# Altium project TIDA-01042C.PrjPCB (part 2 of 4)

## Sheet SV601272A-TM4C_Main.SchDoc
size 431 x 279 mm; Date: Not shown in title block; ApprovedBy: Not shown in title block; CheckedBy: Not shown in title block; Author: Not shown in title block; CompanyName: Not shown in title block; Engineer: Not shown in title block; Organization: Not shown in title block; Address1: Not shown in title block; Address2: Not shown in title block; Address3: Not shown in title block; Address4: Not shown in title block; DocumentNumber: 10; Revision: Use project parameter SCH_Rev; SheetNumber: 10; SheetTotal: 11; PageSetup: Record=PageOptions¦CenterHorizontal=True¦CenterVertical=True¦PrintScale=1.00¦XCorrection=1.00¦YCorrection=1.00¦PrintKind=0¦BorderSize=5000000¦LeftOffset=0¦BottomOffset=0¦Orientation=2¦PaperLength=1000¦PaperWidth=1000¦Scale=100¦PaperSource=15¦PrintQuality=600¦MediaType=1¦DitherType=10¦PaperKind=Letter¦PrintScaleMode=1

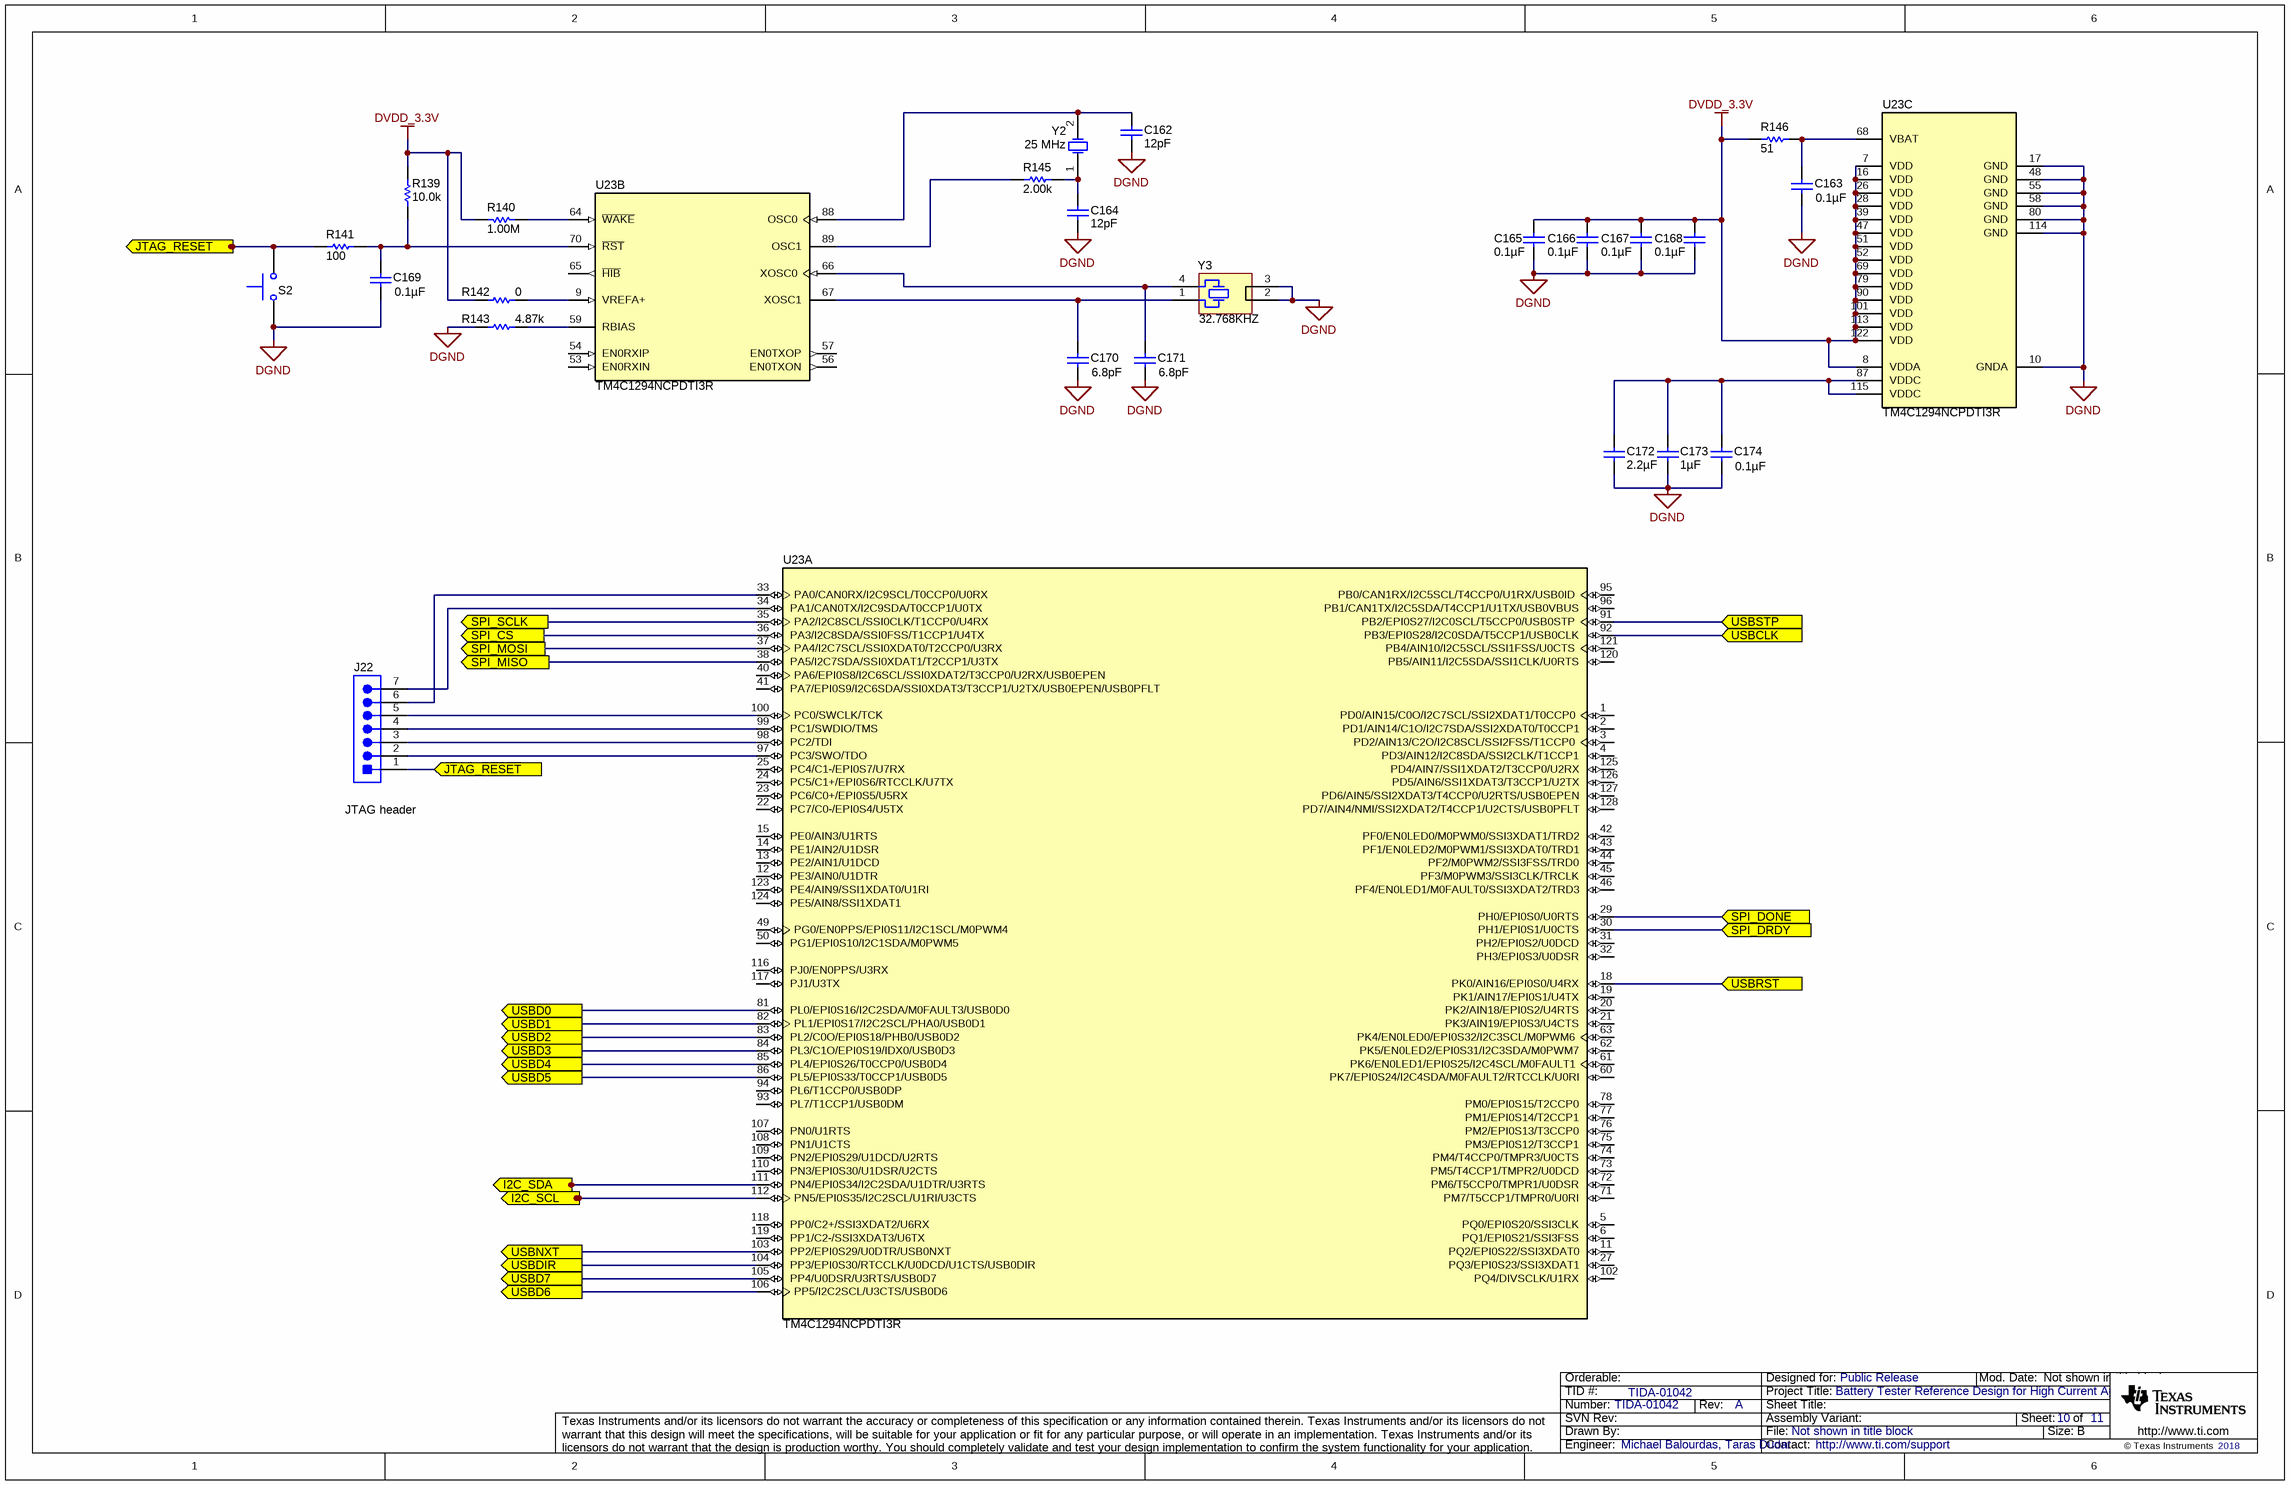
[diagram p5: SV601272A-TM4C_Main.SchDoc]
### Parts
C162  ValueDisplayed: 12pF  [0603]  (hidden comment: C0603C120J5GACTU)
C163  ValueDisplayed: 0.1µF  [0603]  (hidden comment: 06033C104JAT2A)
C164  ValueDisplayed: 12pF  [0603]  (hidden comment: C0603C120J5GACTU)
C165  ValueDisplayed: 0.1µF  [0603]  (hidden comment: 06033C104JAT2A)
C166  ValueDisplayed: 0.1µF  [0603]  (hidden comment: 06033C104JAT2A)
C167  ValueDisplayed: 0.1µF  [0603]  (hidden comment: 06033C104JAT2A)
C168  ValueDisplayed: 0.1µF  [0603]  (hidden comment: 06033C104JAT2A)
C169  ValueDisplayed: 0.1µF  [0603]  (hidden comment: 06033C104JAT2A)
C170  ValueDisplayed: 6.8pF  [0603]  (hidden comment: 06035A6R8CAT2A)
C171  ValueDisplayed: 6.8pF  [0603]  (hidden comment: 06035A6R8CAT2A)
C172  ValueDisplayed: 2.2µF  [0603]  (hidden comment: GRM188R6YA225KA12D)
C173  ValueDisplayed: 1µF  [0603]  (hidden comment: GRM188R71E105KA12D)
C174  ValueDisplayed: 0.1µF  [0603]  (hidden comment: 06033C104JAT2A)
J22  TSW-107-07-G-S  [TSW-107-07-G-S]  (value not drawn)
R139  ValueDisplayed: 10.0k  [0603]  (hidden comment: CRCW060310K0FKEA)
R140  ValueDisplayed: 1.00M  [0603]  (hidden comment: CRCW06031M00FKEA)
R141  ValueDisplayed: 100  [0603]  (hidden comment: CRCW0603100RFKEA)
R142  ValueDisplayed: 0  [0603]  (hidden comment: CRCW06030000Z0EA)
R143  ValueDisplayed: 4.87k  [0603]  (hidden comment: CRCW06034K87FKEA)
R145  ValueDisplayed: 2.00k  [0603]  (hidden comment: CRCW06032K00FKEA)
R146  ValueDisplayed: 51  [0603]  (hidden comment: CRCW060351R0JNEA)
S2  TL1015AF160QG  [SW_TL1015AF160QG]  (value not drawn)
U23  TM4C1294NCPDTI3R  [PDT0128A]  (parts A,B,C of 3)
Y2  Frequency: 25 MHz  [XTAL_ABM3]  (hidden comment: ABM3-25.000MHZ-D2Y-T)
Y3  Frequency: 32.768KHZ  [Seiko_SSP-T]  (hidden comment: SSPT7F-7PF20-R)

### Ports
I2C_SCL, I2C_SDA, JTAG_RESET, SPI_CS, SPI_DONE, SPI_DRDY, SPI_MISO, SPI_MOSI, SPI_SCLK, USBCLK, USBD0, USBD1, USBD2, USBD3, USBD4, USBD5, USBD6, USBD7, USBDIR, USBNXT, USBRST, USBSTP

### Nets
DGND: C162.2 C163.1 C164.2 C165.1 C166.1 C167.1 C168.1 C169.1 C170.1 C171.1 C172.2 C173.2 C174.1 R143.2 S2.1 U23.10(GNDA) U23.17(GND) U23.48(GND) U23.55(GND) U23.58(GND) U23.80(GND) U23.114(GND) Y3.2 Y3.3
DVDD_3.3V: C165.2 C166.2 C167.2 C168.2 R139.2 R140.2 R142.1 R146.1 U23.7(VDD) U23.8(VDDA) U23.16(VDD) U23.26(VDD) U23.28(VDD) U23.39(VDD) U23.47(VDD) U23.51(VDD) U23.52(VDD) U23.69(VDD) U23.79(VDD) U23.90(VDD) U23.101(VDD) U23.113(VDD) U23.122(VDD)
I2C_SCL: U23.112(PN5/EPI0S35/I2C2SCL/U1RI/U3CTS) ; port I2C_SCL
I2C_SDA: U23.111(PN4/EPI0S34/I2C2SDA/U1DTR/U3RTS) ; port I2C_SDA
JTAG_RESET: J22.1 R141.1 S2.2 ; port JTAG_RESET
SPI_CS: U23.36(PA3/I2C8SDA/SSI0FSS/T1CCP1/U4TX) ; port SPI_CS
SPI_DONE: U23.29(PH0/EPI0S0/U0RTS) ; port SPI_DONE
SPI_DRDY: U23.30(PH1/EPI0S1/U0CTS) ; port SPI_DRDY
SPI_MISO: U23.38(PA5/I2C7SDA/SSI0XDAT1/T2CCP1/U3TX) ; port SPI_MISO
SPI_MOSI: U23.37(PA4/I2C7SCL/SSI0XDAT0/T2CCP0/U3RX) ; port SPI_MOSI
SPI_SCLK: U23.35(PA2/I2C8SCL/SSI0CLK/T1CCP0/U4RX) ; port SPI_SCLK
USBCLK: U23.92(PB3/EPI0S28/I2C0SDA/T5CCP1/USB0CLK) ; port USBCLK
USBD0: U23.81(PL0/EPI0S16/I2C2SDA/M0FAULT3/USB0D0) ; port USBD0
USBD1: U23.82(PL1/EPI0S17/I2C2SCL/PHA0/USB0D1) ; port USBD1
USBD2: U23.83(PL2/C0O/EPI0S18/PHB0/USB0D2) ; port USBD2
USBD3: U23.84(PL3/C1O/EPI0S19/IDX0/USB0D3) ; port USBD3
USBD4: U23.85(PL4/EPI0S26/T0CCP0/USB0D4) ; port USBD4
USBD5: U23.86(PL5/EPI0S33/T0CCP1/USB0D5) ; port USBD5
USBD6: U23.106(PP5/I2C2SCL/U3CTS/USB0D6) ; port USBD6
USBD7: U23.105(PP4/U0DSR/U3RTS/USB0D7) ; port USBD7
USBDIR: U23.104(PP3/EPI0S30/RTCCLK/U0DCD/U1CTS/USB0DIR) ; port USBDIR
USBNXT: U23.103(PP2/EPI0S29/U0DTR/USB0NXT) ; port USBNXT
USBRST: U23.18(PK0/AIN16/EPI0S0/U4RX) ; port USBRST
USBSTP: U23.91(PB2/EPI0S27/I2C0SCL/T5CCP0/USB0STP) ; port USBSTP
NetC162_1: C162.1 U23.88(OSC0) Y2.2(OSC2)
NetC163_2: C163.2 R146.2 U23.68(VBAT)
NetC164_1: C164.1 R145.1 Y2.1(OSC1)
NetC169_2: C169.2 R139.1 R141.2 U23.70(~{RST})
NetC170_2: C170.2 U23.67(XOSC1) Y3.1
NetC171_2: C171.2 U23.66(XOSC0) Y3.4
NetC172_1: C172.1 C173.1 C174.2 U23.87(VDDC) U23.115(VDDC)
NetJ22_2: J22.2 U23.97(PC3/SWO/TDO)
NetJ22_3: J22.3 U23.98(PC2/TDI)
NetJ22_4: J22.4 U23.99(PC1/SWDIO/TMS)
NetJ22_5: J22.5 U23.100(PC0/SWCLK/TCK)
NetJ22_6: J22.6 U23.33(PA0/CAN0RX/I2C9SCL/T0CCP0/U0RX)
NetJ22_7: J22.7 U23.34(PA1/CAN0TX/I2C9SDA/T0CCP1/U0TX)
NetR140_1: R140.1 U23.64(~{WAKE})
NetR142_2: R142.2 U23.9(VREFA+)
NetR143_1: R143.1 U23.59(RBIAS)
NetR145_2: R145.2 U23.89(OSC1)

Not connected (* = marked no-connect by the designer): U23 1(PD0/AIN15/C0O/I2C7SCL/SSI2XDAT1/T0CCP0) 2(PD1/AIN14/C1O/I2C7SDA/SSI2XDAT0/T0CCP1) 3(PD2/AIN13/C2O/I2C8SCL/SSI2FSS/T1CCP0) 4(PD3/AIN12/I2C8SDA/SSI2CLK/T1CCP1) 5(PQ0/EPI0S20/SSI3CLK) 6(PQ1/EPI0S21/SSI3FSS) 11(PQ2/EPI0S22/SSI3XDAT0) 12(PE3/AIN0/U1DTR) 13(PE2/AIN1/U1DCD) 14(PE1/AIN2/U1DSR) 15(PE0/AIN3/U1RTS) 19(PK1/AIN17/EPI0S1/U4TX) 20(PK2/AIN18/EPI0S2/U4RTS) 21(PK3/AIN19/EPI0S3/U4CTS) 22(PC7/C0-/EPI0S4/U5TX) 23(PC6/C0+/EPI0S5/U5RX) 24(PC5/C1+/EPI0S6/RTCCLK/U7TX) 25(PC4/C1-/EPI0S7/U7RX) 27(PQ3/EPI0S23/SSI3XDAT1) 31(PH2/EPI0S2/U0DCD) 32(PH3/EPI0S3/U0DSR) 40(PA6/EPI0S8/I2C6SCL/SSI0XDAT2/T3CCP0/U2RX/USB0EPEN) 41(PA7/EPI0S9/I2C6SDA/SSI0XDAT3/T3CCP1/U2TX/USB0EPEN/USB0PFLT) 42(PF0/EN0LED0/M0PWM0/SSI3XDAT1/TRD2) 43(PF1/EN0LED2/M0PWM1/SSI3XDAT0/TRD1) 44(PF2/M0PWM2/SSI3FSS/TRD0) 45(PF3/M0PWM3/SSI3CLK/TRCLK) 46(PF4/EN0LED1/M0FAULT0/SSI3XDAT2/TRD3) 49(PG0/EN0PPS/EPI0S11/I2C1SCL/M0PWM4) 50(PG1/EPI0S10/I2C1SDA/M0PWM5) 53(EN0RXIN) 54(EN0RXIP) 56(EN0TXON) 57(EN0TXOP) 60(PK7/EPI0S24/I2C4SDA/M0FAULT2/RTCCLK/U0RI) 61(PK6/EN0LED1/EPI0S25/I2C4SCL/M0FAULT1) 62(PK5/EN0LED2/EPI0S31/I2C3SDA/M0PWM7) 63(PK4/EN0LED0/EPI0S32/I2C3SCL/M0PWM6) 65(~{HIB}) 71(PM7/T5CCP1/TMPR0/U0RI) 72(PM6/T5CCP0/TMPR1/U0DSR) 73(PM5/T4CCP1/TMPR2/U0DCD) 74(PM4/T4CCP0/TMPR3/U0CTS) 75(PM3/EPI0S12/T3CCP1) 76(PM2/EPI0S13/T3CCP0) 77(PM1/EPI0S14/T2CCP1) 78(PM0/EPI0S15/T2CCP0) 93(PL7/T1CCP1/USB0DM) 94(PL6/T1CCP0/USB0DP) 95(PB0/CAN1RX/I2C5SCL/T4CCP0/U1RX/USB0ID) 96(PB1/CAN1TX/I2C5SDA/T4CCP1/U1TX/USB0VBUS) 102(PQ4/DIVSCLK/U1RX) 107(PN0/U1RTS) 108(PN1/U1CTS) 109(PN2/EPI0S29/U1DCD/U2RTS) 110(PN3/EPI0S30/U1DSR/U2CTS) 116(PJ0/EN0PPS/U3RX) 117(PJ1/U3TX) 118(PP0/C2+/SSI3XDAT2/U6RX) 119(PP1/C2-/SSI3XDAT3/U6TX) 120(PB5/AIN11/I2C5SDA/SSI1CLK/U0RTS) 121(PB4/AIN10/I2C5SCL/SSI1FSS/U0CTS) 123(PE4/AIN9/SSI1XDAT0/U1RI) 124(PE5/AIN8/SSI1XDAT1) 125(PD4/AIN7/SSI1XDAT2/T3CCP0/U2RX) 126(PD5/AIN6/SSI1XDAT3/T3CCP1/U2TX) 127(PD6/AIN5/SSI2XDAT3/T4CCP0/U2RTS/USB0EPEN) 128(PD7/AIN4/NMI/SSI2XDAT2/T4CCP1/U2CTS/USB0PFLT)

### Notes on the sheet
- (near J22) JTAG header

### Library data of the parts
C162 C164 = C0603C120J5GACTU: CAP, CERM, 12 pF, 50 V, +/- 5%, C0G/NP0, 0603; Manufacturer: Kemet; Polarized: N; CompType: Capacitor; Value: 12pF; U/M: EA; Cap_F: 0.000000000012; Tolerance_%: 5; Value1: Unknown; VDC_V: 50; Value2: 50V; TaMin_C: -55; TaMax_C: 125; AEC Category: Q200
C163 C165-C169 C174 = 06033C104JAT2A: CAP, CERM, 0.1 µF, 25 V, +/- 5%, X7R, 0603; Manufacturer: AVX; Polarized: N; CompType: Capacitor; Value: 0.1uF; U/M: EA; Cap_F: 0.0000001; Tolerance_%: 5; ESR_ohm: 0.05; Value1: 0.05 ohm; VDC_V: 25; Value2: 25V; TaMin_C: -55; TaMax_C: 125; AEC Category: Q200
C170 C171 = 06035A6R8CAT2A: CAP, CERM, 6.8 pF, 50 V, +/- 4%, C0G/NP0, 0603; Manufacturer: AVX; Polarized: N; CompType: Capacitor; Value: 6.8pF; U/M: EA; Cap_F: 0.0000000000068; Tolerance_%: 4; ESR_ohm: 0.505; Value1: 0.505 ohm; VDC_V: 50; Value2: 50V; TaMin_C: -55; TaMax_C: 125; AEC Category: Q200
C172 = GRM188R6YA225KA12D: CAP, CERM, 2.2 µF, 35 V, +/- 10%, X5R, 0603; Manufacturer: MuRata; Polarized: N; CompType: Capacitor; Value: 2.2uF; U/M: EA; Cap_F: 0.0000022; Tolerance_%: 10; Value1: Unknown; VDC_V: 35; Value2: 35V; TaMin_C: -55; TaMax_C: 85; AEC Category: Q200
C173 = GRM188R71E105KA12D: CAP, CERM, 1 µF, 25 V, +/- 10%, X7R, 0603; Manufacturer: MuRata; Polarized: N; CompType: Capacitor; Value: 1uF; U/M: EA; Cap_F: 0.000001; Tolerance_%: 10; Value1: Unknown; VDC_V: 25; Value2: 25V; TaMin_C: -55; TaMax_C: 125; AEC Category: Q200
J22 = TSW-107-07-G-S: Header, 100mil, 7x1, Gold, TH; Manufacturer: Samtec; SymbolCreator: a0411947; U/M: EA
R139 = CRCW060310K0FKEA: RES, 10.0 k, 1%, 0.1 W, 0603; Manufacturer: Vishay-Dale; CompType: Resistor; Value: 10.0k; Res_ohm: 10000; Value_Code: 10k0; Tolerance_%: 1; Power_W: 0.1; Value2: 0.1W; VDC_V: 75; TempCo: 100 ppm/C; EIA_Code: E96; U/M: EA; AEC Category: Q200
R140 = CRCW06031M00FKEA: RES, 1.00 M, 1%, 0.1 W, 0603; Manufacturer: Vishay-Dale; CompType: Resistor; Value: 1.00Meg; Res_ohm: 1000000; Value_Code: 1M00; Tolerance_%: 1; Power_W: 0.1; Value2: 0.1W; VDC_V: 75; TempCo: 100 ppm/C; EIA_Code: E96; U/M: EA; AEC Category: Q200
R141 = CRCW0603100RFKEA: RES, 100, 1%, 0.1 W, 0603; Manufacturer: Vishay-Dale; CompType: Resistor; Value: 100; Value_Code: 100R; Tolerance_%: 1; Power_W: 0.1; Value2: 0.1W; VDC_V: 75; TempCo: 100 ppm/C; EIA_Code: E96; U/M: EA; AEC Category: Q200
R142 = CRCW06030000Z0EA: RES, 0, 5%, 0.1 W, 0603; Manufacturer: Vishay-Dale; CompType: Resistor; Value: 0; Value_Code: 0000; Tolerance_%: 5; Power_W: 0.1; Value2: 0.1W; VDC_V: 75; TempCo: 200 ppm/C; EIA_Code: E24; U/M: EA; AEC Category: Q200
R143 = CRCW06034K87FKEA: RES, 4.87 k, 1%, 0.1 W, 0603; Manufacturer: Vishay-Dale; CompType: Resistor; Value: 4.87k; Res_ohm: 4870; Value_Code: 4k87; Tolerance_%: 1; Power_W: 0.1; Value2: 0.1W; VDC_V: 75; TempCo: 100 ppm/C; EIA_Code: E96; U/M: EA; AEC Category: Q200
R145 = CRCW06032K00FKEA: RES, 2.00 k, 1%, 0.1 W, 0603; Manufacturer: Vishay-Dale; CompType: Resistor; Value: 2.00k; Res_ohm: 2000; Value_Code: 2k00; Tolerance_%: 1; Power_W: 0.1; Value2: 0.1W; VDC_V: 75; TempCo: 100 ppm/C; EIA_Code: E96; U/M: EA; AEC Category: Q200
R146 = CRCW060351R0JNEA: RES, 51, 5%, 0.1 W, 0603; Manufacturer: Vishay-Dale; CompType: Resistor; Value: 51; Value_Code: 51R0; Tolerance_%: 5; Power_W: 0.1; Value2: 0.1W; VDC_V: 75; TempCo: 200 ppm/C; EIA_Code: E24; U/M: EA; AEC Category: Q200
S2 = TL1015AF160QG: Switch, Tactile, SPST-NO, 0.05A, 12V, SMT; Manufacturer: E-Switch; SymbolCreator: a0412235; VDC_V: 12; SwitchFunction: Off-Mom; PositionCount: 1; CurrentRating_mA: 50
U23 = CMP-0029864-2: Tiva C Series Microcontroller, 1024 KB Flash, 256 KB SRAM, 12 Bit, 20 Channels, -40 to 85 degC, 128-Pin TQFP (PDT), Green (RoHS & no Sb/Br), Tape and Reel; Manufacturer: Texas Instruments; ADC Channels: 20; CPU: ARM Cortex-M4; Flash: 1024 KB; ADC Resolution: 12 Bits; Max Speed: 120 MHz; SRAM: 256 KB; SizeAreaWB_mm2: 324.0; SizeArea_mm2: 256.0; SizeX_mm: 16.0; SizeZ_mm: 1.2; CompType: IC
Y2 = ABM3-25.000MHZ-D2Y-T: Crystal, 25 MHz, 18 pF, SMD; Manufacturer: Abracon Corportation; SymbolCreator: a0412235; U/M: EA; TaMin_C: -40; TaMax_C: 85; Frequency Stability: ±30ppm
Y3 = SSPT7F-7PF20-R: CRYSTAL, 32.768KHZ, 7PF, SMD; Manufacturer: Seiko Instruments; SymbolCreator: x0208325; U/M: EA; TaMin_C: -40; TaMax_C: 85; Frequency Stability: ±20ppm

## Sheet SV601272A-TM4C_Power.SchDoc
size 431 x 279 mm; Date: Not shown in title block; ApprovedBy: Not shown in title block; CheckedBy: Not shown in title block; Author: Not shown in title block; CompanyName: Not shown in title block; Engineer: Not shown in title block; Organization: Not shown in title block; Address1: Not shown in title block; Address2: Not shown in title block; Address3: Not shown in title block; Address4: Not shown in title block; DocumentNumber: 11; Revision: Use project parameter SCH_Rev; SheetNumber: 11; SheetTotal: 11; PageSetup: Record=PageOptions¦CenterHorizontal=True¦CenterVertical=True¦PrintScale=1.00¦XCorrection=1.00¦YCorrection=1.00¦PrintKind=0¦BorderSize=5000000¦LeftOffset=0¦BottomOffset=0¦Orientation=2¦PaperLength=1000¦PaperWidth=1000¦Scale=100¦PaperSource=15¦PrintQuality=600¦MediaType=1¦DitherType=10¦PaperKind=Letter¦PrintScaleMode=1

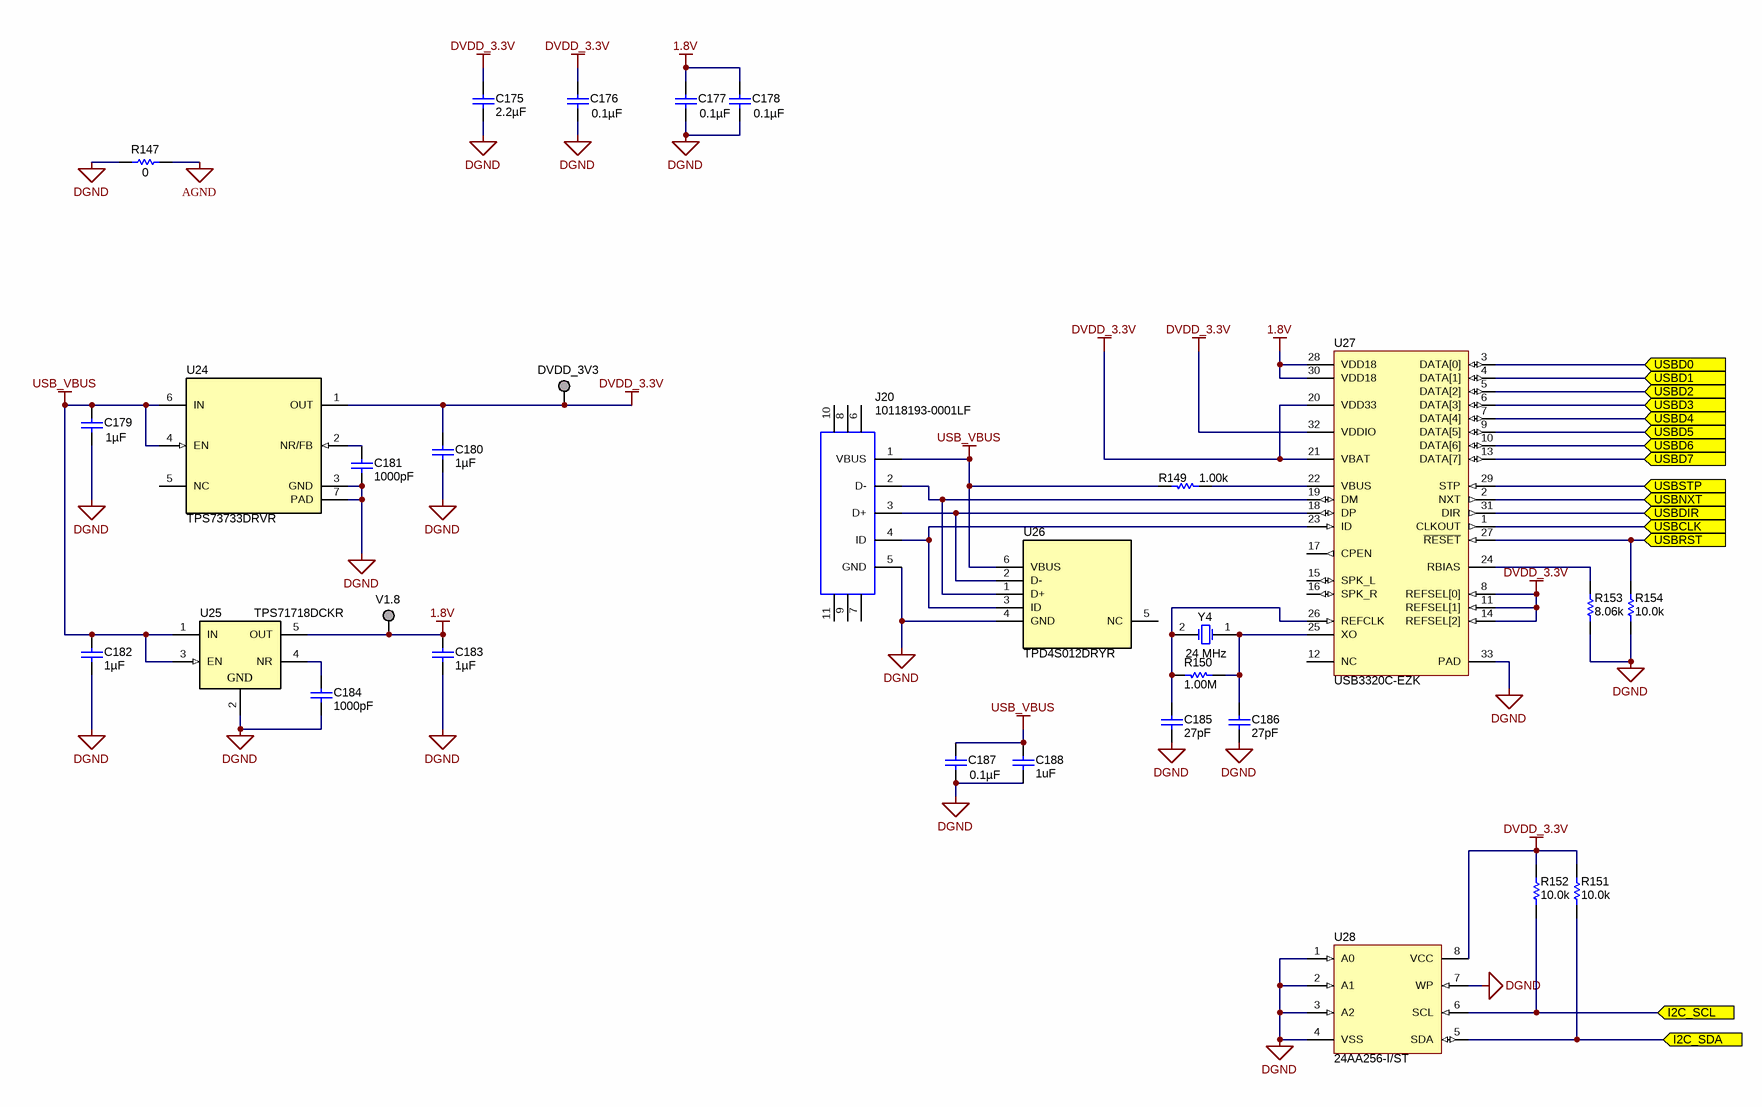
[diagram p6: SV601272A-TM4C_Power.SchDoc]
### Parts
C175  ValueDisplayed: 2.2µF  [0603]  (hidden comment: GRM188R6YA225KA12D)
C176  ValueDisplayed: 0.1µF  [0603]  (hidden comment: 06033C104JAT2A)
C177  ValueDisplayed: 0.1µF  [0603]  (hidden comment: 06033C104JAT2A)
C178  ValueDisplayed: 0.1µF  [0603]  (hidden comment: 06033C104JAT2A)
C179  ValueDisplayed: 1µF  [0603]  (hidden comment: GRM188R71E105KA12D)
C180  ValueDisplayed: 1µF  [0603]  (hidden comment: GRM188R71E105KA12D)
C181  ValueDisplayed: 1000pF  [0603]  (hidden comment: 06031C102JAT2A)
C182  ValueDisplayed: 1µF  [0603]  (hidden comment: GRM188R71E105KA12D)
C183  ValueDisplayed: 1µF  [0603]  (hidden comment: GRM188R71E105KA12D)
C184  ValueDisplayed: 1000pF  [0603]  (hidden comment: 06031C102JAT2A)
C185  ValueDisplayed: 27pF  [0603]  (hidden comment: 06035A270JAT2A)
C186  ValueDisplayed: 27pF  [0603]  (hidden comment: 06035A270JAT2A)
C187  ValueDisplayed: 0.1µF  [0603]  (hidden comment: 06033C104JAT2A)
C188  ValueDisplayed: 1uF  [0603]  (hidden comment: Capacitor)
DVDD_3V3  Pogo Pad  [PogoPad]  (value not drawn)  (no BOM)
J20  10118193-0001LF  [FCI_10118193-0001LF]
R147  ValueDisplayed: 0  [0603]  (hidden comment: Resistor)
R149  ValueDisplayed: 1.00k  [0603]  (hidden comment: CRCW06031K00FKEA)
R150  ValueDisplayed: 1.00M  [0603]  (hidden comment: CRCW06031M00FKEA)
R151  ValueDisplayed: 10.0k  [0603]  (hidden comment: CRCW060310K0FKEA)
R152  ValueDisplayed: 10.0k  [0603]  (hidden comment: CRCW060310K0FKEA)
R153  ValueDisplayed: 8.06k  [0603]  (hidden comment: CRCW06038K06FKEA)
R154  ValueDisplayed: 10.0k  [0603]  (hidden comment: CRCW060310K0FKEA)
U24  TPS73733DRVR  [DRV0006A]
U25  TPS71718DCKR  [DCK0005A_N]
U26  TPD4S012DRYR  [DRY0006A]
U27  USB3320C-EZK  [Microchip_32QFN-3304-5x5B]
U28  24AA256-I/ST  [TSSOP-8]
V1.8  Pogo Pad  [PogoPad]  (value not drawn)  (no BOM)
Y4  Frequency: 24 MHz  [XTAL_ABM3]  (hidden comment: ABM3-24.000MHZ-D2Y-T)

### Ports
I2C_SCL, I2C_SDA, USBCLK, USBD0, USBD1, USBD2, USBD3, USBD4, USBD5, USBD6, USBD7, USBDIR, USBNXT, USBRST, USBSTP

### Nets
1.8V: C177.2 C178.2 C183.1 U25.5(OUT) U27.28(VDD18) U27.30(VDD18) V1.8.1
AGND: R147.2
DGND: C175.2 C176.1 C177.1 C178.1 C179.2 C180.2 C181.2 C182.2 C183.2 C184.2 C185.1 C186.1 C187.1 C188.2 J20.5(GND) R147.1 R153.1 R154.1 U24.3(GND) U24.7(PAD) U25.2(GND) U26.4(GND) U27.33(PAD) U28.1(A0) U28.2(A1) U28.3(A2) U28.4(VSS) U28.7(WP)
DVDD_3.3V: C175.1 C176.2 C180.1 DVDD_3V3.1 R151.2 R152.2 U24.1(OUT) U27.8(REFSEL[0]) U27.11(REFSEL[1]) U27.14(REFSEL[2]) U27.20(VDD33) U27.21(VBAT) U27.32(VDDIO) U28.8(VCC)
USB_VBUS: C179.1 C182.1 C187.2 C188.1 J20.1(VBUS) R149.2 U24.4(EN) U24.6(IN) U25.1(IN) U25.3(EN) U26.6(VBUS)
I2C_SCL: R152.1 U28.6(SCL) ; port I2C_SCL
I2C_SDA: R151.1 U28.5(SDA) ; port I2C_SDA
USBCLK: U27.1(CLKOUT) ; port USBCLK
USBD0: U27.3(DATA[0]) ; port USBD0
USBD1: U27.4(DATA[1]) ; port USBD1
USBD2: U27.5(DATA[2]) ; port USBD2
USBD3: U27.6(DATA[3]) ; port USBD3
USBD4: U27.7(DATA[4]) ; port USBD4
USBD5: U27.9(DATA[5]) ; port USBD5
USBD6: U27.10(DATA[6]) ; port USBD6
USBD7: U27.13(DATA[7]) ; port USBD7
USBDIR: U27.31(DIR) ; port USBDIR
USBNXT: U27.2(NXT) ; port USBNXT
USBRST: R154.2 U27.27(~{RESET}) ; port USBRST
USBSTP: U27.29(STP) ; port USBSTP
NetC181_1: C181.1 U24.2(NR/FB)
NetC184_1: C184.1 U25.4(NR)
NetC185_2: C185.2 R150.2 U27.26(REFCLK) Y4.2(OSC2)
NetC186_2: C186.2 R150.1 U27.25(XO) Y4.1(OSC1)
NetJ20_2: J20.2(D-) U26.1(D+) U27.19(DM)
NetJ20_3: J20.3(D+) U26.2(D-) U27.18(DP)
NetJ20_4: J20.4(ID) U26.3(ID) U27.23(ID)
NetR149_1: R149.1 U27.22(VBUS)
NetR153_2: R153.2 U27.24(RBIAS)

Not connected (* = marked no-connect by the designer): J20 6 7 8 9 10 11; U24 5(NC); U26 5(NC); U27 12(NC) 15(SPK_L) 16(SPK_R) 17(CPEN)

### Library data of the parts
C175 = GRM188R6YA225KA12D: as C172 on sheet SV601272A-TM4C_Main
C176-C178 C187 = 06033C104JAT2A: as C163 on sheet SV601272A-TM4C_Main
C179 C180 C182 C183 = GRM188R71E105KA12D: as C173 on sheet SV601272A-TM4C_Main
C181 C184 = 06031C102JAT2A: CAP, CERM, 1000 pF, 100 V, +/- 5%, X7R, 0603; Manufacturer: AVX; Polarized: N; CompType: Capacitor; Value: 1000pF; U/M: EA; Cap_F: 0.000000001; Tolerance_%: 5; ESR_ohm: 0.276; Value1: 0.276 ohm; VDC_V: 100; Value2: 100V; TaMin_C: -55; TaMax_C: 125; AEC Category: Q200
C185 C186 = 06035A270JAT2A: CAP, CERM, 27 pF, 50 V, +/- 5%, C0G/NP0, 0603; Manufacturer: AVX; Polarized: N; CompType: Capacitor; Value: 27pF; U/M: EA; Cap_F: 0.000000000027; Tolerance_%: 5; ESR_ohm: 0.232; Value1: 0.232 ohm; VDC_V: 50; Value2: 50V; TaMin_C: -55; TaMax_C: 125; AEC Category: Q200
C188 = CMP-0007405-4: CAP, CERM, 1 uF, 25 V, +/- 10%, X7R, 0603; PartNumber: GRM188R71E105KA12D; Manufacturer: MuRata; Polarized: N; Value: 1uF; U/M: EA; Cap_F: 1µF; Value1: Unknown; VDC_V: 25V; TaMin_C: -55°C; TaMax_C: 125°C; AEC Category: Q200; SizeArea_mm2: 1.28; SizeAreaWB_mm2: 4.68; SizeX_mm: 1.6; SizeY_mm: 0.8; SizeZ_mm: 1
DVDD_3V3 V1.8 = PogoPad: Pad for Pogo Pin Connector; SymbolCreator: codlsc
J20 = CMP-0065029-1: Connector, Receptacle, USB Micro B, R/A, SMT; Manufacturer: FCI; CNHeader: False; Gender: Female; Row_Count: 1; Pitch_mm: 0.65; ContactFinish: Gold; CT: True
R147 = CMP-0025874-3: RES, 0, 5%, 0.1 W, 0603; PartNumber: ERJ-3GEY0R00V; Manufacturer: Panasonic; Value: 0; Value_Code: 0000; Power_W: 100mW; Value2: 0.1W; VDC_V: 50V; TempCo: 600 ppm/C; EIA_Code: E24; U/M: EA; AEC Category: Q200; SizeArea_mm2: 1.28; SizeX_mm: 1.6; SizeY_mm: 0.8; SizeZ_mm: 1
R149 = CRCW06031K00FKEA: RES, 1.00 k, 1%, 0.1 W, 0603; Manufacturer: Vishay-Dale; CompType: Resistor; Value: 1.00k; Res_ohm: 1000; Value_Code: 1k00; Tolerance_%: 1; Power_W: 0.1; Value2: 0.1W; VDC_V: 75; TempCo: 100 ppm/C; EIA_Code: E96; U/M: EA; AEC Category: Q200
R150 = CRCW06031M00FKEA: as R140 on sheet SV601272A-TM4C_Main
R151 R152 R154 = CRCW060310K0FKEA: as R139 on sheet SV601272A-TM4C_Main
R153 = CRCW06038K06FKEA: RES, 8.06 k, 1%, 0.1 W, 0603; Manufacturer: Vishay-Dale; CompType: Resistor; Value: 8.06k; Res_ohm: 8060; Value_Code: 8k06; Tolerance_%: 1; Power_W: 0.1; Value2: 0.1W; VDC_V: 75; TempCo: 100 ppm/C; EIA_Code: E96; U/M: EA; AEC Category: Q200
U24 = TPS73733DRVR: 1-A Low-Dropout Regulator With Reverse Current Protection, DRV0006A; Manufacturer: Texas Instruments; Alternate PartNumber: TPS73733DRVT; SymbolCreator: a0411947; CompType: IC; U/M: EA
U25 = TPS71718DCKR: Single Output High PSRR LDO, 150 mA, Fixed 1.8 V Output, 2.5 to 6.5 V Input, with Low IQ, 5-pin SC70 (DCK), -40 to 85 degC, Green (RoHS & no Sb/Br); Manufacturer: Texas Instruments; Alternate PartNumber: Equivalent; Accuracy(%): 3; Fixed Output Options(V): 1.8; Iout(Max)(A): 0.15; Iq(Typ)(mA): 0.05; SubFamily: Single Channel LDO; Vdo(Typ)(mV): 170; Vin(Max)(V): 6.5; Vin(Min)(V): 2.5
U26 = CMP-0043122-2: USB ESD Solution with Power Clamp, 4 Channels, -40 to +85 degC, 6-pin SON (DRY), Green (RoHS & no Sb/Br); Manufacturer: Texas Instruments; IO Leakage Current(nA): 10; USB High Speed: TRUE; Breakdown Voltage(Min)(V): 6; IO Capacitance(Typ)(pF): 0.8; AEC Category: Q200; AEC Qualified: N; CompType: IC; SizeAreaWB_mm2: 4.9; SizeArea_mm2: 1.45; SizeX_mm: 1.0; SizeZ_mm: 0.6
U27 = USB3320C-EZK: Highly Integrated Full Featured Hi-Speed USB 2.0 ULPI Transceiver, QFN-32; Manufacturer: Microchip; SymbolCreator: Altium
U28 = 24AA256-I/ST: 256K I2C™ CMOS Serial EEPROM, TSSOP-8; Manufacturer: Microchip; SymbolCreator: a0411947
Y4 = ABM3-24.000MHZ-D2Y-T: Crystal, 24 MHz, 18 pF, SMD; Manufacturer: Abracon Corportation; SymbolCreator: a0412235; U/M: EA; TaMin_C: -40; TaMax_C: 85; Frequency Stability: ±30ppm

## Sheet SV601272A-Controller2.SchDoc: Controller
size 431 x 279 mm; Date: Not shown in title block; ApprovedBy: Not shown in title block; CheckedBy: Not shown in title block; Author: Not shown in title block; CompanyName: Not shown in title block; Engineer: Not shown in title block; Organization: Not shown in title block; Address1: Not shown in title block; Address2: Not shown in title block; Address3: Not shown in title block; Address4: Not shown in title block; DocumentNumber: 4; Revision: Use project parameter SCH_Rev; SheetNumber: 4; SheetTotal: 11; PageSetup: Record=PageOptions¦CenterHorizontal=True¦CenterVertical=True¦PrintScale=1.00¦XCorrection=1.00¦YCorrection=1.00¦PrintKind=0¦BorderSize=5000000¦LeftOffset=0¦BottomOffset=0¦Orientation=2¦PaperLength=1000¦PaperWidth=1000¦Scale=100¦PaperSource=15¦PrintQuality=600¦MediaType=1¦DitherType=10¦PaperKind=Letter¦PrintScaleMode=1

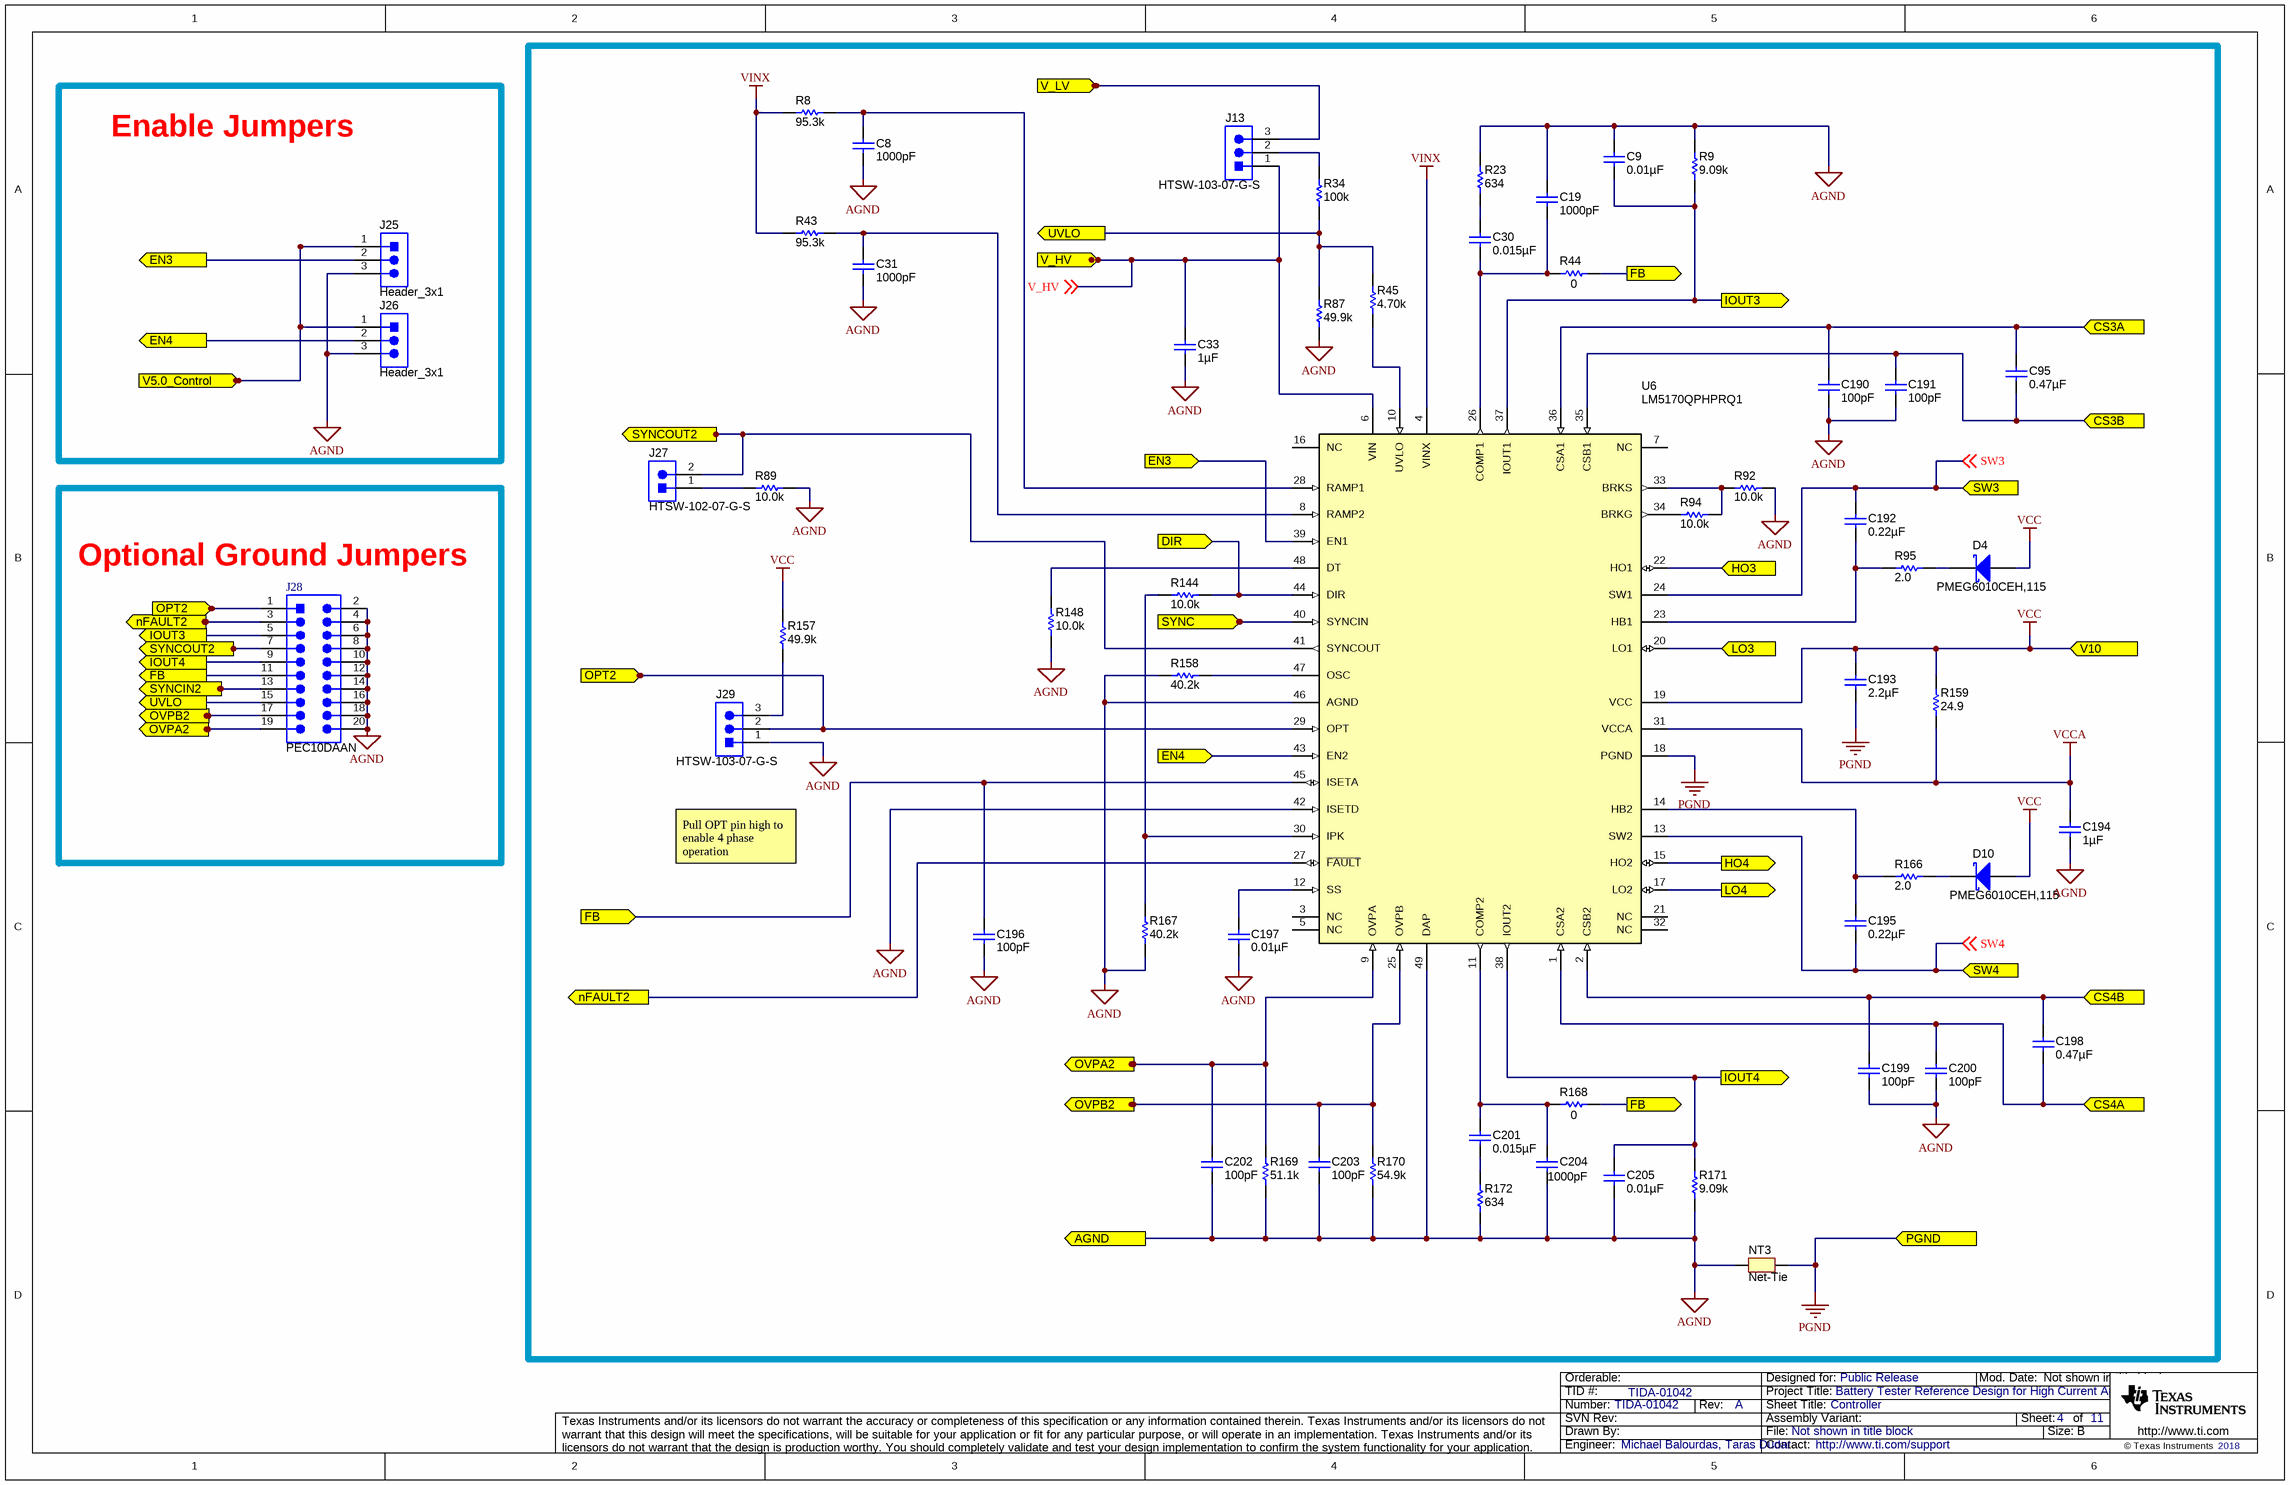
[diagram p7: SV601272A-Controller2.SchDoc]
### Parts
C8  ValueDisplayed: 1000pF  [0603L]  (hidden comment: C1608C0G2A102J080AA)
C9  ValueDisplayed: 0.01µF  [0603L]  (hidden comment: 06031C103KAT2A)
C19  ValueDisplayed: 1000pF  [0603L]  (hidden comment: C1608C0G2A102J080AA)
C30  ValueDisplayed: 0.015µF  [0603L]  (hidden comment: GRM188R71E153KA01D)
C31  ValueDisplayed: 1000pF  [0603L]  (hidden comment: C1608C0G2A102J080AA)
C33  ValueDisplayed: 1µF  [0805_HV]  (hidden comment: C2012X7S2A105K125AB)
C95  ValueDisplayed: 0.47µF  [0603L]  (hidden comment: GRM188R71C474KA88D)
C190  ValueDisplayed: 100pF  [0603L]  (hidden comment: C0603C101J5GACTU)
C191  ValueDisplayed: 100pF  [0603L]  (hidden comment: C0603C101J5GACTU)
C192  ValueDisplayed: 0.22µF  [0603L]  (hidden comment: C1608X7R1H224K080AB)
C193  ValueDisplayed: 2.2µF  [0805_HV]  (hidden comment: C2012X7R1C225K125AB)
C194  ValueDisplayed: 1µF  [0603L]  (hidden comment: GRM188R71E105KA12D)
C195  ValueDisplayed: 0.22µF  [0603L]  (hidden comment: C1608X7R1H224K080AB)
C196  ValueDisplayed: 100pF  [0603L]  (hidden comment: C0603C101J5GACTU)
C197  ValueDisplayed: 0.01µF  [0603L]  (hidden comment: 06031C103KAT2A)
C198  ValueDisplayed: 0.47µF  [0603L]  (hidden comment: GRM188R71C474KA88D)
C199  ValueDisplayed: 100pF  [0603L]  (hidden comment: C0603C101J5GACTU)
C200  ValueDisplayed: 100pF  [0603L]  (hidden comment: C0603C101J5GACTU)
C201  ValueDisplayed: 0.015µF  [0603L]  (hidden comment: GRM188R71E153KA01D)
C202  ValueDisplayed: 100pF  [0603L]  (hidden comment: C0603C101J5GACTU)
C203  ValueDisplayed: 100pF  [0603L]  (hidden comment: C0603C101J5GACTU)
C204  ValueDisplayed: 1000pF  [0603L]  (hidden comment: C1608C0G2A102J080AA)
C205  ValueDisplayed: 0.01µF  [0603L]  (hidden comment: 06031C103KAT2A)
D4  PMEG6010CEH,115  [SOD-123F]
D10  PMEG6010CEH,115  [SOD-123F]
J13  HTSW-103-07-G-S  [Samtec_HTSW-103-07-G-S]
J25  Header_3x1  [Samtec_HTSW-103-07-G-S]
J26  Header_3x1  [Samtec_HTSW-103-07-G-S]
J27  HTSW-102-07-G-S  [Samtec_HTSW-102-07-G-S]
J28  PEC10DAAN  [SULLINS_PEC10DAAN]
J29  HTSW-103-07-G-S  [Samtec_HTSW-103-07-G-S]
NT3  Net-Tie  [Net-Tie_10mil]  (net tie, no BOM)
R8  ValueDisplayed: 95.3k  [0603L]  (hidden comment: CRCW060395K3FKEA)
R9  ValueDisplayed: 9.09k  [0603L]  (hidden comment: CRCW06039K09FKEA)
R23  ValueDisplayed: 634  [0603L]  (hidden comment: CRCW0603634RFKEA)
R34  ValueDisplayed: 100k  [0603]  (hidden comment: CRCW0603100KFKEA)
R43  ValueDisplayed: 95.3k  [0603L]  (hidden comment: CRCW060395K3FKEA)
R44  ValueDisplayed: 0  [0603]  (hidden comment: Resistor)
R45  ValueDisplayed: 4.70k  [0603]  (hidden comment: RC0603FR-074K7L)
R87  ValueDisplayed: 49.9k  [0603]  (hidden comment: ERJ-3EKF4992V)
R89  ValueDisplayed: 10.0k  [0603L]  (hidden comment: CRCW060310K0FKEA)
R92  ValueDisplayed: 10.0k  [0603]  (hidden comment: ERJ-3EKF1002V)
R94  ValueDisplayed: 10.0k  [0603]  (hidden comment: ERJ-3EKF1002V)
R95  ValueDisplayed: 2.0  [0805_HV]  (hidden comment: CRCW08052R00JNEA)
R144  ValueDisplayed: 10.0k  [0603L]  (hidden comment: CRCW060310K0FKEA)
R148  ValueDisplayed: 10.0k  [0603L]  (hidden comment: CRCW060310K0FKEA)
R157  ValueDisplayed: 49.9k  [0603L]  (hidden comment: CRCW060349K9FKEA)
R158  ValueDisplayed: 40.2k  [0603L]  (hidden comment: CRCW060340K2FKEA)
R159  ValueDisplayed: 24.9  [0805L]  (hidden comment: CRCW080524R9FKEA)
R166  ValueDisplayed: 2.0  [0805_HV]  (hidden comment: CRCW08052R00JNEA)
R167  ValueDisplayed: 40.2k  [0603]  (hidden comment: ERJ-3EKF4022V)
R168  ValueDisplayed: 0  [0603]  (hidden comment: Resistor)
R169  ValueDisplayed: 51.1k  [0603L]  (hidden comment: CRCW060351K1FKEA)
R170  ValueDisplayed: 54.9k  [0603L]  (hidden comment: CRCW060354K9FKEA)
R171  ValueDisplayed: 9.09k  [0603L]  (hidden comment: CRCW06039K09FKEA)
R172  ValueDisplayed: 634  [0603L]  (hidden comment: CRCW0603634RFKEA)
U6  LM5170QPHPRQ1  [PHP0048D_L]

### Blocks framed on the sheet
Enable Jumpers: J25 J26
Optional Ground Jumpers: J28

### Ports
AGND, CS3A, CS3B, CS4A, CS4B, DIR, EN3, EN4, FB, HO3, HO4, IOUT3, IOUT4, LO3, LO4, nFAULT2, OPT2, OVPA2, OVPB2, PGND, SW3, SW4, SYNC, SYNCIN2, SYNCOUT2, UVLO, V5.0_Control, V10, V_HV, V_LV

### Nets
AGND: C8.2 C9.1 C19.1 C31.2 C33.2 C190.2 C191.2 C194.2 C196.2 C197.2 C199.2 C200.2 C202.2 C203.2 C204.2 C205.2 J25.3 J26.3 J28.2 J28.4 J28.6 J28.8 J28.10 J28.12 J28.14 J28.16 J28.18 J28.20 J29.1 NT3.1 R9.2 R23.2 R87.1 R89.2 R92.1 R148.1 R158.1 R167.1 R169.1 R170.1 R171.1 R172.1 U6.42(ISETD) U6.46(AGND) U6.49(DAP) ; port AGND
PGND: C193.2 NT3.2 U6.18(PGND) ; port PGND
V_HV: C33.1 J13.1 U6.6(VIN) ; off-sheet V_HV, port V_HV
V_LV: J13.3 ; port V_LV
VCC: C193.1 D4.2(A) D10.2(A) R157.2 R159.2 U6.19(VCC) ; port V10
VCCA: C194.1 R159.1 U6.31(VCCA)
VINX: R8.1 R43.1 U6.4(VINX)
CS3A: C95.1 C190.1 U6.36(CSA1) ; port CS3A
CS3B: C95.2 C191.1 U6.35(CSB1) ; port CS3B
CS4A: C198.2 C200.1 U6.1(CSA2) ; port CS4A
CS4B: C198.1 C199.1 U6.2(CSB2) ; port CS4B
DIR: R144.2 U6.44(DIR) ; port DIR
EN3: J25.2 U6.39(EN1) ; port EN3
EN4: J26.2 U6.43(EN2) ; port EN4
FB: C196.1 J28.11 R44.2 R168.2 U6.45(ISETA) ; port FB
HO3: U6.22(HO1) ; port HO3
HO4: U6.15(HO2) ; port HO4
IOUT3: C9.2 J28.5 R9.1 U6.37(IOUT1) ; port IOUT3
IOUT4: C205.1 J28.9 R171.2 U6.38(IOUT2) ; port IOUT4
LO3: U6.20(LO1) ; port LO3
LO4: U6.17(LO2) ; port LO4
nFAULT2: J28.3 U6.27(~{FAULT}) ; port nFAULT2
OPT2: J28.1 J29.2 U6.29(OPT) ; port OPT2
OVPA2: C202.1 J28.19 R169.2 U6.9(OVPA) ; port OVPA2
OVPB2: C203.1 J28.17 R170.2 U6.25(OVPB) ; port OVPB2
SW3: C192.1 U6.24(SW1) ; off-sheet SW3, port SW3
SW4: C195.2 U6.13(SW2) ; off-sheet SW4, port SW4
SYNC: U6.40(SYNCIN) ; port SYNC
SYNCIN2: J28.13 ; port SYNCIN2
SYNCOUT2: J27.2 J28.7 U6.41(SYNCOUT) ; port SYNCOUT2
UVLO: J28.15 R34.1 R45.2 R87.2 ; port UVLO
V5.0_Control: J25.1 J26.1 ; port V5.0_Control
NetC8_1: C8.1 R8.2 U6.28(RAMP1)
NetC19_2: C19.2 C30.2 R44.1 U6.26(COMP1)
NetC30_1: C30.1 R23.1
NetC31_1: C31.1 R43.2 U6.8(RAMP2)
NetC192_2: C192.2 R95.1 U6.23(HB1)
NetC195_1: C195.1 R166.1 U6.14(HB2)
NetC197_1: C197.1 U6.12(SS)
NetC201_1: C201.1 C204.1 R168.1 U6.11(COMP2)
NetC201_2: C201.2 R172.2
NetD4_1: D4.1(K) R95.2
NetD10_1: D10.1(K) R166.2
NetJ13_2: J13.2 R34.2
NetJ27_1: J27.1 R89.1
NetJ29_3: J29.3 R157.1
NetR45_1: R45.1 U6.10(UVLO)
NetR92_2: R92.2 R94.1 U6.33(BRKS)
NetR94_2: R94.2 U6.34(BRKG)
NetR144_1: R144.1 R167.2 U6.30(IPK)
NetR148_2: R148.2 U6.48(DT)
NetR158_2: R158.2 U6.47(OSC)

Not connected (* = marked no-connect by the designer): U6 3(NC) 5(NC) 7(NC) 16(NC) 21(NC) 32(NC)

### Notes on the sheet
- Pull OPT pin high to enable 4 phase operation

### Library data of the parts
C8 C19 C31 C204 = C1608C0G2A102J080AA: CAP, CERM, 1000 pF, 100 V, +/- 5%, C0G/NP0, 0603; Manufacturer: TDK; Polarized: N; CompType: Capacitor; Value: 1000pF; U/M: EA; Cap_F: 0.000000001; Tolerance_%: 5; ESR_ohm: 0.0589; Value1: 0.0589 ohm; VDC_V: 100; Value2: 100V; TaMin_C: -55; TaMax_C: 125; Cap_Case: 0603; AEC Category: Q200
C9 C197 C205 = 06031C103KAT2A: CAP, CERM, 0.01 µF, 100 V, +/- 10%, X7R, 0603; Manufacturer: AVX; Polarized: N; CompType: Capacitor; Value: 0.01uF; U/M: EA; Cap_F: 0.00000001; Tolerance_%: 10; ESR_ohm: 0.098; Value1: 0.098 ohm; VDC_V: 100; Value2: 100V; TaMin_C: -55; TaMax_C: 125; Cap_Case: 0603
C30 C201 = GRM188R71E153KA01D: CAP, CERM, 0.015 µF, 25 V, +/- 10%, X7R, 0603; Manufacturer: MuRata; Polarized: N; CompType: Capacitor; Value: 0.015uF; U/M: EA; Cap_F: 0.000000015; Tolerance_%: 10; Value1: Unknown; VDC_V: 25; Value2: 25V; TaMin_C: -55; TaMax_C: 125; Cap_Case: 0603
C33 = C2012X7S2A105K125AB: CAP, CERM, 1 µF, 100 V, +/- 10%, X7S, 0805; Manufacturer: TDK; Polarized: N; CompType: Capacitor; Value: 1uF; U/M: EA; Cap_F: 0.000001; Tolerance_%: 10; Value1: Unknown; VDC_V: 100; Value2: 100V; TaMin_C: -55; TaMax_C: 125; Cap_Case: 0805; AEC Category: Q200
C95 C198 = GRM188R71C474KA88D: CAP, CERM, 0.47 µF, 16 V, +/- 10%, X7R, 0603; Manufacturer: MuRata; Polarized: N; CompType: Capacitor; Value: 0.47uF; U/M: EA; Cap_F: 0.00000047; Tolerance_%: 10; Value1: Unknown; VDC_V: 16; Value2: 16V; TaMin_C: -55; TaMax_C: 125; Cap_Case: 0603; AEC Category: Q200
C190 C191 C199 C200 C202 C203 = C0603C101J5GACTU: CAP, CERM, 100 pF, 50 V, +/- 5%, C0G/NP0, 0603; Manufacturer: Kemet; Polarized: N; CompType: Capacitor; Value: 100pF; U/M: EA; Cap_F: 0.0000000001; Tolerance_%: 5; Value1: Unknown; VDC_V: 50; Value2: 50V; TaMin_C: -55; TaMax_C: 125; Cap_Case: 0603; AEC Category: Q200
C192 C195 = C1608X7R1H224K080AB: CAP, CERM, 0.22 µF, 50 V, +/- 10%, X7R, 0603; Manufacturer: TDK; Polarized: N; CompType: Capacitor; Value: 0.22uF; U/M: EA; Cap_F: 0.00000022; Tolerance_%: 10; Value1: Unknown; VDC_V: 50; Value2: 50V; TaMin_C: -55; TaMax_C: 125; Cap_Case: 0603
C193 = C2012X7R1C225K125AB: CAP, CERM, 2.2 µF, 16 V, +/- 10%, X7R, 0805; Manufacturer: TDK; CompType: Capacitor; Value: 2.2uF; U/M: EA; Tolerance_%: 10; VDC_V: 16; Polarized: N; Cap_F: 0.0000022; ESR_ohm: 0.0049; Value1: 0.0049 ohm; Value2: 16V; TaMin_C: -55; TaMax_C: 125; Cap_Case: 0805; AEC Category: Q200
C194 = GRM188R71E105KA12D: CAP, CERM, 1 µF, 25 V, +/- 10%, X7R, 0603; Manufacturer: MuRata; Polarized: N; CompType: Capacitor; Value: 1uF; U/M: EA; Cap_F: 0.000001; Tolerance_%: 10; Value1: Unknown; VDC_V: 25; Value2: 25V; TaMin_C: -55; TaMax_C: 125; Cap_Case: 0603
C196 = C0603C101J5GACTU: CAP, CERM, 100 pF, 50 V, +/- 5%, C0G/NP0, 0603; Manufacturer: Kemet; Polarized: N; CompType: Capacitor; Value: 100pF; U/M: EA; Cap_F: 0.0000000001; Tolerance_%: 5; Value1: Unknown; VDC_V: 50; Value2: 50V; TaMin_C: -55; TaMax_C: 125; Cap_Case: 0603; AEC Category: Q200; SizeArea_mm2: 1.28; SizeAreaWB_mm2: 4.68; SizeX_mm: 1.6; SizeY_mm: 0.8; SizeZ_mm: 1
D4 D10 = PMEG6010CEH,115: Diode, Schottky, 60 V, 1 A, SOD-123F; Manufacturer: NXP Semiconductor; U/M: EA; Vf_V: 0.57; Value: 60V; Value1: 1A; Value2: 0.57V; Io_A: 1; Vr_V: 60; TJmax_C: 150
J13 J29 = HTSW-103-07-G-S: Header, 100mil, 3x1, Gold, TH; Manufacturer: Samtec; SymbolCreator: a0799628; U/M: EA
J25 J26 = CMP-0075484-1: Header, 100mil, 3x1, Gold, TH; PartNumber: HTSW-103-07-G-S; Manufacturer: Samtec; CNHeader: True; CT: False; Green_Lifecycle: Active; Green_REACh: Passed
J27 = HTSW-102-07-G-S: Header, 100mil, 2x1, Gold, TH; Manufacturer: Samtec; SymbolCreator: a0412235; U/M: EA
J28 = CMP-0054623-2: Header, 2.54mm, 10x2, Tin, TH; Manufacturer: Sullins Connector Solutions; Current_A: 3A; Green_Lifecycle: Not Set; Shrouded: N; Gender: Male; Green_REACh: Incomplete; Row_Count: 2; RowSpacing_mm: 2.54; Cert_UL: Y
NT3 = Net-Tie: Single point connection between nets.; SymbolCreator: codlsc
R8 R43 = CRCW060395K3FKEA: RES, 95.3 k, 1%, 0.1 W, 0603; Manufacturer: Vishay-Dale; CompType: Resistor; Value: 95.3k; Res_ohm: 95300; Value_Code: 95k3; Tolerance_%: 1; Power_W: 0.1; Value2: 0.1W; VDC_V: 75; TempCo: 100 ppm/C; EIA_Code: E96; U/M: EA
R9 R171 = CRCW06039K09FKEA: RES, 9.09 k, 1%, 0.1 W, 0603; Manufacturer: Vishay-Dale; CompType: Resistor; Value: 9.09k; Res_ohm: 9090; Value_Code: 9k09; Tolerance_%: 1; Power_W: 0.1; Value2: 0.1W; VDC_V: 75; TempCo: 100 ppm/C; EIA_Code: E96; U/M: EA
R23 R172 = CRCW0603634RFKEA: RES, 634, 1%, 0.1 W, 0603; Manufacturer: Vishay-Dale; CompType: Resistor; Value: 634; Value_Code: 634R; Tolerance_%: 1; Power_W: 0.1; Value2: 0.1W; VDC_V: 75; TempCo: 100 ppm/C; EIA_Code: E96; U/M: EA
R34 = CMP-0021990-4: RES, 100 k, 1%, 0.1 W, AEC-Q200 Grade 0, 0603; Manufacturer: Vishay-Dale; Power_W: 100mW; TempCo: 100 ppm/C; Value: 100k; EIA_Code: E96; SizeX_mm: 1.6; SizeY_mm: 0.8; SizeZ_mm: 1; Value2: 0.1W; SizeArea_mm2: 1.28; CompType: Resistor; AEC Qualified: Y; VDC_V: 75V; AEC Category: Q200; AEC Grade: 0
R44 R168 = CMP-0025874-3: as R147 on sheet SV601272A-TM4C_Power
R45 = CMP-0023153-3: RES, 4.70 k, 1%, 0.1 W, 0603; Manufacturer: Yageo America; Power_W: 100mW; TempCo: 200 ppm/C; Value_Code: 4k70; U/M: EA; Value: 4.70k; Res_ohm: 4.7k; SizeX_mm: 1.6; SizeY_mm: 0.8; SizeZ_mm: 1; Value2: 0.1W; SizeArea_mm2: 1.28; CompType: Resistor; VDC_V: 150V; AEC Category: Q200
R87 = CMP-0022705-3: RES, 49.9 k, 1%, 0.1 W, AEC-Q200 Grade 0, 0603; Manufacturer: Panasonic; Power_W: 100mW; TempCo: 100 ppm/C; Value_Code: 49k9; U/M: EA; Value: 49.9k; EIA_Code: E96; SizeX_mm: 1.6; SizeY_mm: 0.8; SizeZ_mm: 1; Value2: 0.1W; SizeArea_mm2: 1.28; CompType: Resistor; AEC Qualified: Y; VDC_V: 75V; AEC Grade: 0; AEC Category: Q200
R89 R144 = CRCW060310K0FKEA: RES, 10.0 k, 1%, 0.1 W, 0603; Manufacturer: Vishay-Dale; CompType: Resistor; Value: 10.0k; Res_ohm: 10000; Value_Code: 10k0; Tolerance_%: 1; Power_W: 0.1; Value2: 0.1W; VDC_V: 75; TempCo: 100 ppm/C; EIA_Code: E96; U/M: EA
R92 R94 = CMP-0022684-3: RES, 10.0 k, 1%, 0.1 W, 0603; Manufacturer: Panasonic; Power_W: 100mW; TempCo: 100 ppm/C; Value_Code: 10k0; U/M: EA; Value: 10.0k; EIA_Code: E96; Res_ohm: 10k; SizeX_mm: 1.6; SizeY_mm: 0.8; SizeZ_mm: 1; Value2: 0.1W; SizeArea_mm2: 1.28; CompType: Resistor; VDC_V: 75V; AEC Category: Q200
R95 R166 = CRCW08052R00JNEA: RES, 2.0, 5%, 0.125 W, 0805; Manufacturer: Vishay-Dale; CompType: Resistor; Value: 2.0; Res_ohm: 2; Value_Code: 2R00; Tolerance_%: 5; Power_W: 0.125; Value2: 0.125W; VDC_V: 150; TempCo: 200 ppm/C; EIA_Code: E24; U/M: EA; AEC Category: Q200
R148 = CRCW060310K0FKEA: RES, 10.0 k, 1%, 0.1 W, 0603; Manufacturer: Vishay-Dale; CompType: Resistor; Value: 10.0k; Res_ohm: 10000; Value_Code: 10k0; Tolerance_%: 1; Power_W: 0.1; Value2: 0.1W; VDC_V: 75; TempCo: 100 ppm/C; EIA_Code: E96; U/M: EA; SizeArea_mm2: 1.28; SizeX_mm: 1.6; SizeY_mm: 0.8; AEC Category: Q200
R157 = CRCW060349K9FKEA: RES, 49.9 k, 1%, 0.1 W, 0603; Manufacturer: Vishay-Dale; CompType: Resistor; Value: 49.9k; Res_ohm: 49900; Value_Code: 49k9; Tolerance_%: 1; Power_W: 0.1; Value2: 0.1W; VDC_V: 75; TempCo: 100 ppm/C; EIA_Code: E96; U/M: EA
R158 = CRCW060340K2FKEA: RES, 40.2 k, 1%, 0.1 W, 0603; Manufacturer: Vishay-Dale; CompType: Resistor; Value: 40.2k; Res_ohm: 40200; Value_Code: 40k2; Tolerance_%: 1; Power_W: 0.1; Value2: 0.1W; VDC_V: 75; TempCo: 100 ppm/C; EIA_Code: E96; U/M: EA; SizeArea_mm2: 1.28; SizeX_mm: 1.6; SizeY_mm: 0.8; AEC Category: Q200
R159 = CRCW080524R9FKEA: RES, 24.9, 1%, 0.125 W, 0805; Manufacturer: Vishay-Dale; CompType: Resistor; Value: 24.9; Value_Code: 24R9; Tolerance_%: 1; Power_W: 0.125; Value2: 0.125W; VDC_V: 150; TempCo: 100 ppm/C; EIA_Code: E96; U/M: EA
R167 = CMP-0022700-3: RES, 40.2 k, 1%, 0.1 W, AEC-Q200 Grade 0, 0603; Manufacturer: Panasonic; Power_W: 100mW; TempCo: 100 ppm/C; Value_Code: 40k2; U/M: EA; Value: 40.2k; EIA_Code: E96; SizeX_mm: 1.6; SizeY_mm: 0.8; SizeZ_mm: 1; Value2: 0.1W; SizeArea_mm2: 1.28; CompType: Resistor; AEC Qualified: Y; VDC_V: 75V; AEC Grade: 0; AEC Category: Q200
R169 = CRCW060351K1FKEA: RES, 51.1 k, 1%, 0.1 W, 0603; Manufacturer: Vishay-Dale; CompType: Resistor; Value: 51.1k; Res_ohm: 51100; Value_Code: 51k1; Tolerance_%: 1; Power_W: 0.1; Value2: 0.1W; VDC_V: 75; TempCo: 100 ppm/C; EIA_Code: E96; U/M: EA
R170 = CRCW060354K9FKEA: RES, 54.9 k, 1%, 0.1 W, 0603; Manufacturer: Vishay-Dale; CompType: Resistor; Value: 54.9k; Res_ohm: 54900; Value_Code: 54k9; Tolerance_%: 1; Power_W: 0.1; Value2: 0.1W; VDC_V: 75; TempCo: 100 ppm/C; EIA_Code: E96; U/M: EA
U6 = LM5170QPHPRQ1: Dual Channel 48V-12V Bidirectional Current Controller, PHP0048D; Manufacturer: Texas Instruments; Alternate PartNumber: LM5170QPHPTQ1; SymbolCreator: Altium; CompType: IC; U/M: EA

## Sheet SV601272A-Power2 REV2.SchDoc: Power Stage
size 431 x 279 mm; Date: Not shown in title block; ApprovedBy: Not shown in title block; CheckedBy: Not shown in title block; Author: Not shown in title block; CompanyName: Not shown in title block; Engineer: Not shown in title block; Organization: Not shown in title block; Address1: Not shown in title block; Address2: Not shown in title block; Address3: Not shown in title block; Address4: Not shown in title block; DocumentNumber: 5; Revision: Use project parameter SCH_Rev; SheetNumber: 5; SheetTotal: 11; PageSetup: Record=PageOptions¦CenterHorizontal=True¦CenterVertical=True¦PrintScale=0.62¦XCorrection=1.00¦YCorrection=1.00¦PrintKind=0¦BorderSize=5000000¦LeftOffset=0¦BottomOffset=0¦Orientation=2¦PaperLength=1000¦PaperWidth=1000¦Scale=100¦PaperSource=15¦PrintQuality=600¦MediaType=1¦DitherType=10¦PrintScaleMode=1¦PaperKind=Letter (8.5 x 11")¦PaperIndex=1

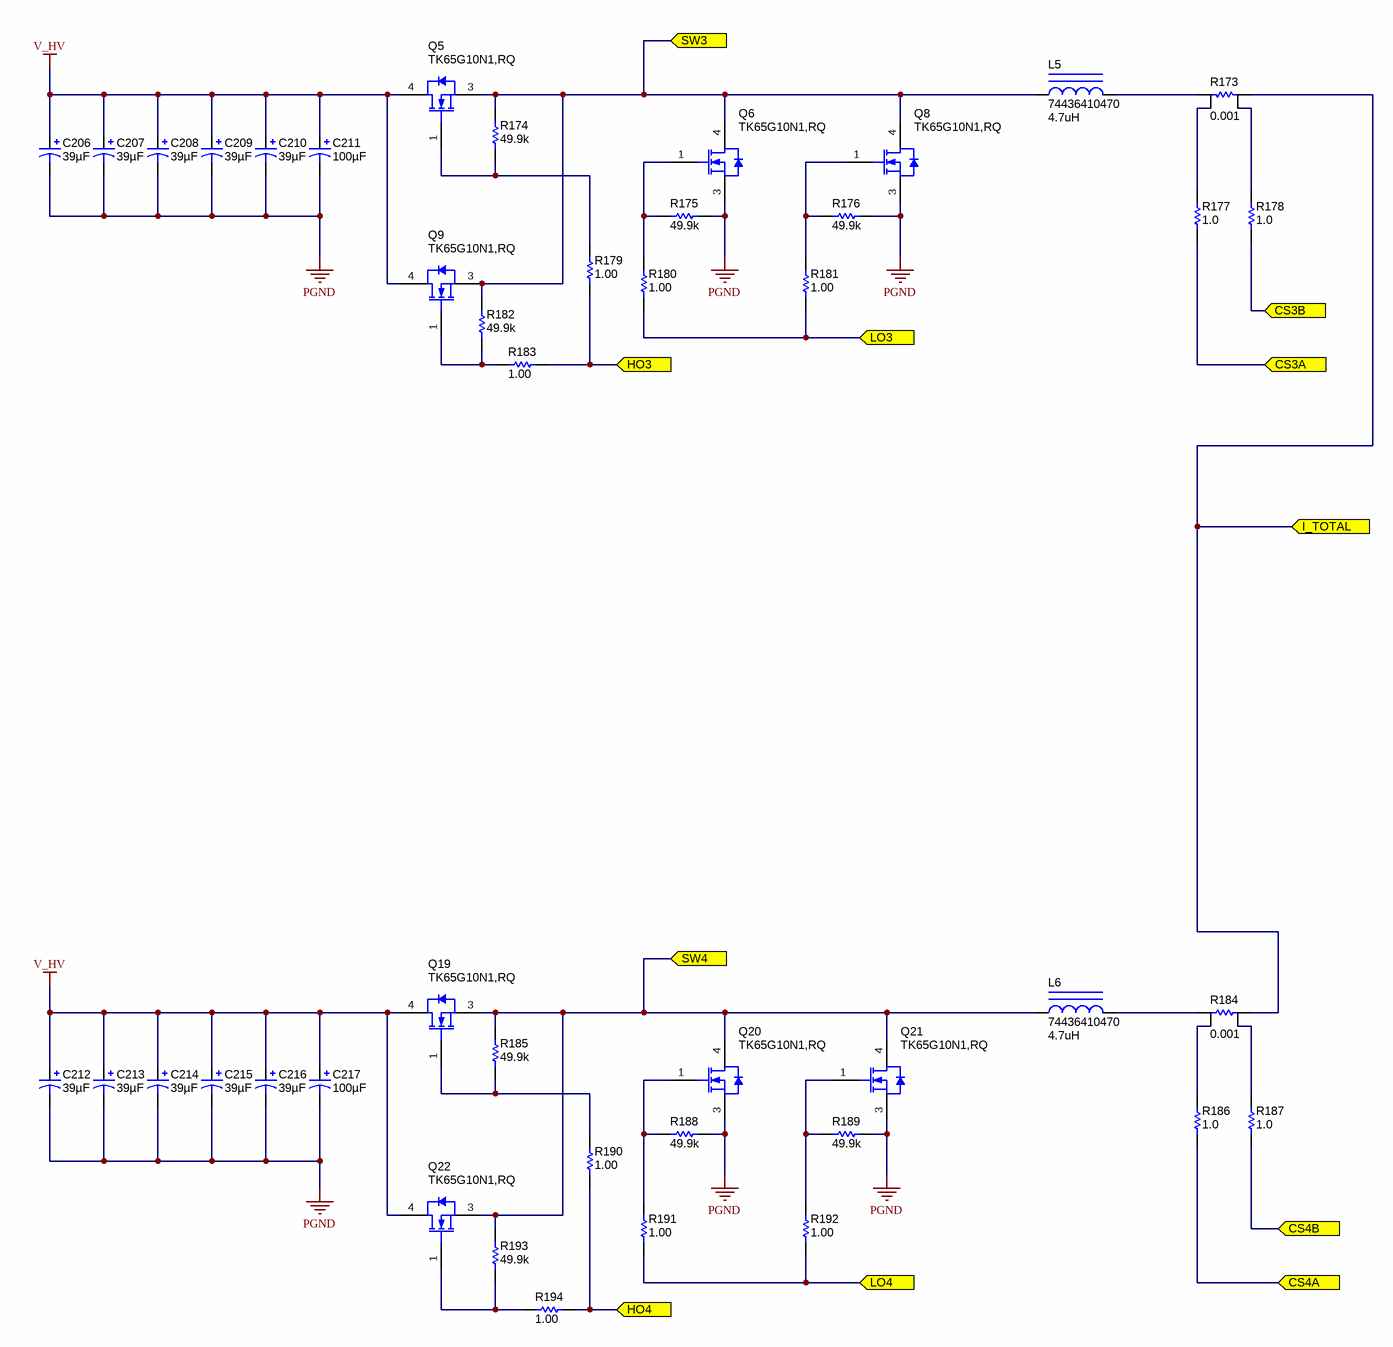
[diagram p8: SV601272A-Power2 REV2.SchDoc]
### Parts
C206  ValueDisplayed: 39µF  [HXA_JA0]  (hidden comment: HHXA800ARA390MJA0G)
C207  ValueDisplayed: 39µF  [HXA_JA0]  (hidden comment: HHXA800ARA390MJA0G)
C208  ValueDisplayed: 39µF  [HXA_JA0]  (hidden comment: HHXA800ARA390MJA0G)
C209  ValueDisplayed: 39µF  [HXA_JA0]  (hidden comment: HHXA800ARA390MJA0G)
C210  ValueDisplayed: 39µF  [HXA_JA0]  (hidden comment: HHXA800ARA390MJA0G)
C211  ValueDisplayed: 100µF  [CAPSMT_62_LH0]  (hidden comment: EMVH101GDA101MLH0S)
C212  ValueDisplayed: 39µF  [HXA_JA0]  (hidden comment: HHXA800ARA390MJA0G)
C213  ValueDisplayed: 39µF  [HXA_JA0]  (hidden comment: HHXA800ARA390MJA0G)
C214  ValueDisplayed: 39µF  [HXA_JA0]  (hidden comment: HHXA800ARA390MJA0G)
C215  ValueDisplayed: 39µF  [HXA_JA0]  (hidden comment: HHXA800ARA390MJA0G)
C216  ValueDisplayed: 39µF  [HXA_JA0]  (hidden comment: HHXA800ARA390MJA0G)
C217  ValueDisplayed: 100µF  [CAPSMT_62_LH0]  (hidden comment: EMVH101GDA101MLH0S)
L5  74436410470  value 4.7uH  [WE-HCF_2818]
L6  74436410470  value 4.7uH  [WE-HCF_2818]
Q5  TK65G10N1,RQ  [DDPAK]
Q6  TK65G10N1,RQ  [DDPAK]
Q8  TK65G10N1,RQ  [DDPAK]
Q9  TK65G10N1,RQ  [DDPAK]
Q19  TK65G10N1,RQ  [DDPAK]
Q20  TK65G10N1,RQ  [DDPAK]
Q21  TK65G10N1,RQ  [DDPAK]
Q22  TK65G10N1,RQ  [DDPAK]
R173  ValueDisplayed: 0.001  [RES_WSL2726]  (hidden comment: WSL27261L000FEB)
R174  ValueDisplayed: 49.9k  [0805_HV]  (hidden comment: CRCW080549K9FKEA)
R175  ValueDisplayed: 49.9k  [0805_HV]  (hidden comment: CRCW080549K9FKEA)
R176  ValueDisplayed: 49.9k  [0805_HV]  (hidden comment: CRCW080549K9FKEA)
R177  ValueDisplayed: 1.0  [0603L]  (hidden comment: CRCW06031R00JNEA)
R178  ValueDisplayed: 1.0  [0603L]  (hidden comment: CRCW06031R00JNEA)
R179  ValueDisplayed: 1.00  [0805_HV]  (hidden comment: CRCW08051R00FKEA)
R180  ValueDisplayed: 1.00  [0805_HV]  (hidden comment: CRCW08051R00FKEA)
R181  ValueDisplayed: 1.00  [0805_HV]  (hidden comment: CRCW08051R00FKEA)
R182  ValueDisplayed: 49.9k  [0805_HV]  (hidden comment: CRCW080549K9FKEA)
R183  ValueDisplayed: 1.00  [0805_HV]  (hidden comment: CRCW08051R00FKEA)
R184  ValueDisplayed: 0.001  [RES_WSL2726]  (hidden comment: WSL27261L000FEB)
R185  ValueDisplayed: 49.9k  [0805_HV]  (hidden comment: CRCW080549K9FKEA)
R186  ValueDisplayed: 1.0  [0603L]  (hidden comment: CRCW06031R00JNEA)
R187  ValueDisplayed: 1.0  [0603L]  (hidden comment: CRCW06031R00JNEA)
R188  ValueDisplayed: 49.9k  [0805_HV]  (hidden comment: CRCW080549K9FKEA)
R189  ValueDisplayed: 49.9k  [0805_HV]  (hidden comment: CRCW080549K9FKEA)
R190  ValueDisplayed: 1.00  [0805_HV]  (hidden comment: CRCW08051R00FKEA)
R191  ValueDisplayed: 1.00  [0805_HV]  (hidden comment: CRCW08051R00FKEA)
R192  ValueDisplayed: 1.00  [0805_HV]  (hidden comment: CRCW08051R00FKEA)
R193  ValueDisplayed: 49.9k  [0805_HV]  (hidden comment: CRCW080549K9FKEA)
R194  ValueDisplayed: 1.00  [0805_HV]  (hidden comment: CRCW08051R00FKEA)

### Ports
CS3A, CS3B, CS4A, CS4B, HO3, HO4, I_TOTAL, LO3, LO4, SW3, SW4

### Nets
PGND: C206.2(-) C207.2(-) C208.2(-) C209.2(-) C210.2(-) C211.2(-) C212.2(-) C213.2(-) C214.2(-) C215.2(-) C216.2(-) C217.2(-) Q6.3(S) Q8.3(S) Q20.3(S) Q21.3(S) R175.2 R176.2 R188.2 R189.2
V_HV: C206.1(+) C207.1(+) C208.1(+) C209.1(+) C210.1(+) C211.1(+) C212.1(+) C213.1(+) C214.1(+) C215.1(+) C216.1(+) C217.1(+) Q5.4(D) Q9.4(D) Q19.4(D) Q22.4(D)
CS3A: R177.1 ; port CS3A
CS3B: R178.1 ; port CS3B
CS4A: R186.1 ; port CS4A
CS4B: R187.1 ; port CS4B
HO3: R179.1 R183.1 ; port HO3
HO4: R190.1 R194.1 ; port HO4
I_TOTAL: R173.2 R184.1 ; port I_TOTAL
LO3: R180.1 R181.1 ; port LO3
LO4: R191.1 R192.1 ; port LO4
SW3: L5.2 Q5.3(S) Q6.4(D) Q8.4(D) Q9.3(S) R174.1 R182.1 ; port SW3
SW4: L6.1 Q19.3(S) Q20.4(D) Q21.4(D) Q22.3(S) R185.2 R193.2 ; port SW4
NetL5_1: L5.1 R173.1
NetL6_2: L6.2 R184.2
NetQ5_1: Q5.1(G) R174.2 R179.2
NetQ6_1: Q6.1(G) R175.1 R180.2
NetQ8_1: Q8.1(G) R176.1 R181.2
NetQ9_1: Q9.1(G) R182.2 R183.2
NetQ19_1: Q19.1(G) R185.1 R190.2
NetQ20_1: Q20.1(G) R188.1 R191.2
NetQ21_1: Q21.1(G) R189.1 R192.2
NetQ22_1: Q22.1(G) R193.1 R194.2
NetR173_3: R173.3 R177.2
NetR173_4: R173.4 R178.2
NetR184_3: R184.3 R187.2
NetR184_4: R184.4 R186.2

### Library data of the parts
C206-C210 C212-C216 = HHXA800ARA390MJA0G: CAP, Aluminum Polymer, 39 µF, 80 V, +/- 20%, 0.035 ohm, AEC-Q200 Grade 1, D10xL10mm SMD; Manufacturer: Chemi-Con; CompType: Capacitor; U/M: EA; ESR_ohm: 0.035; VDC_V: 80; Tolerance_%: 20; Value: 39uF; Polarized: Y; Cap_F: 0.000039; Value2: 80V; IRMS_A: 1.2; TaMin_C: -55; TaMax_C: 125; Cap_Case: 10X10mm; AEC Category: Q200; AEC Grade: 1
C211 C217 = EMVH101GDA101MLH0S: CAP, AL, 100 µF, 100 V, +/- 20%, 0.24 ohm, SMD; Manufacturer: Chemi-Con; Polarized: Y; CompType: Capacitor; Value: 100uF; U/M: EA; Cap_F: 0.0001; Tolerance_%: 20; VDC_V: 100; Value2: 100V; ESR_ohm: 0.24; IRMS_A: 0.65; TaMin_C: -40; TaMax_C: 125; Cap_Case: LH0
L5 L6 = 744364410470: Inductor, 4.7uH, SMT; Manufacturer: WURTH; SymbolCreator: a0413446; U/M: EA
Q5 Q6 Q8 Q9 Q19-Q22 = TK65G10N1,RQ: MOSFET N CH 100V D2PAK; Manufacturer: Toshiba Semiconductor and Storage; SymbolVersion: use current date i.e. 2008-05-20; CompType: Used in some BOM reports.  Useful for finding later.; U/M: EA, IN, or GM; SymbolCreator: Use a-id; Power - Max: 156W; Current - Continuous Drain (Id) @ 25°C: 65A (Ta); FET Type: MOSFET N-Channel, Metal Oxide; FET Feature: Standard; Vgs(th) (Max) @ Id: 4V @ 1mA; Input Capacitance (Ciss) @ Vds: 5400pF @ 50V; Rds On (Max) @ Id, Vgs: 4.5 mOhm @ 32.5A, 10V; Gate Charge (Qg) @ Vgs: 81nC @ 10V
R173 R184 = WSL27261L000FEB: RES, 0.001, 1%, 3 W, 6.6x3x6.9mm; Manufacturer: Vishay-Dale; CompType: Resistor; U/M: EA; Tolerance_%: 1; Value: 0.001; TempCo: 75 ppm/C; Power_W: 3; Value_Code: 1L000; Value2: 3W; EIA_Code: E96; AEC Category: Q200
R174-R176 R182 R185 R188 R189 R193 = CRCW080549K9FKEA: RES, 49.9 k, 1%, 0.125 W, 0805; Manufacturer: Vishay-Dale; CompType: Resistor; Value: 49.9k; Res_ohm: 49900; Value_Code: 49k9; Tolerance_%: 1; Power_W: 0.125; Value2: 0.125W; VDC_V: 150; TempCo: 100 ppm/C; EIA_Code: E96; U/M: EA
R177 R178 R186 R187 = CRCW06031R00JNEA: RES, 1.0, 5%, 0.1 W, 0603; Manufacturer: Vishay-Dale; CompType: Resistor; Value: 1.0; Res_ohm: 1; Value_Code: 1R00; Tolerance_%: 5; Power_W: 0.1; Value2: 0.1W; VDC_V: 75; TempCo: 200 ppm/C; EIA_Code: E24; U/M: EA; AEC Category: Q200
R179-R181 R183 R190-R192 R194 = CRCW08051R00FKEA: RES, 1.00, 1%, 0.125 W, 0805; Manufacturer: Vishay-Dale; CompType: Resistor; Value: 1.00; Res_ohm: 1; Value_Code: 1R00; Power_W: 0.125; Value2: 0.125W; VDC_V: 150; TempCo: 100 ppm/C; EIA_Code: E96; U/M: EA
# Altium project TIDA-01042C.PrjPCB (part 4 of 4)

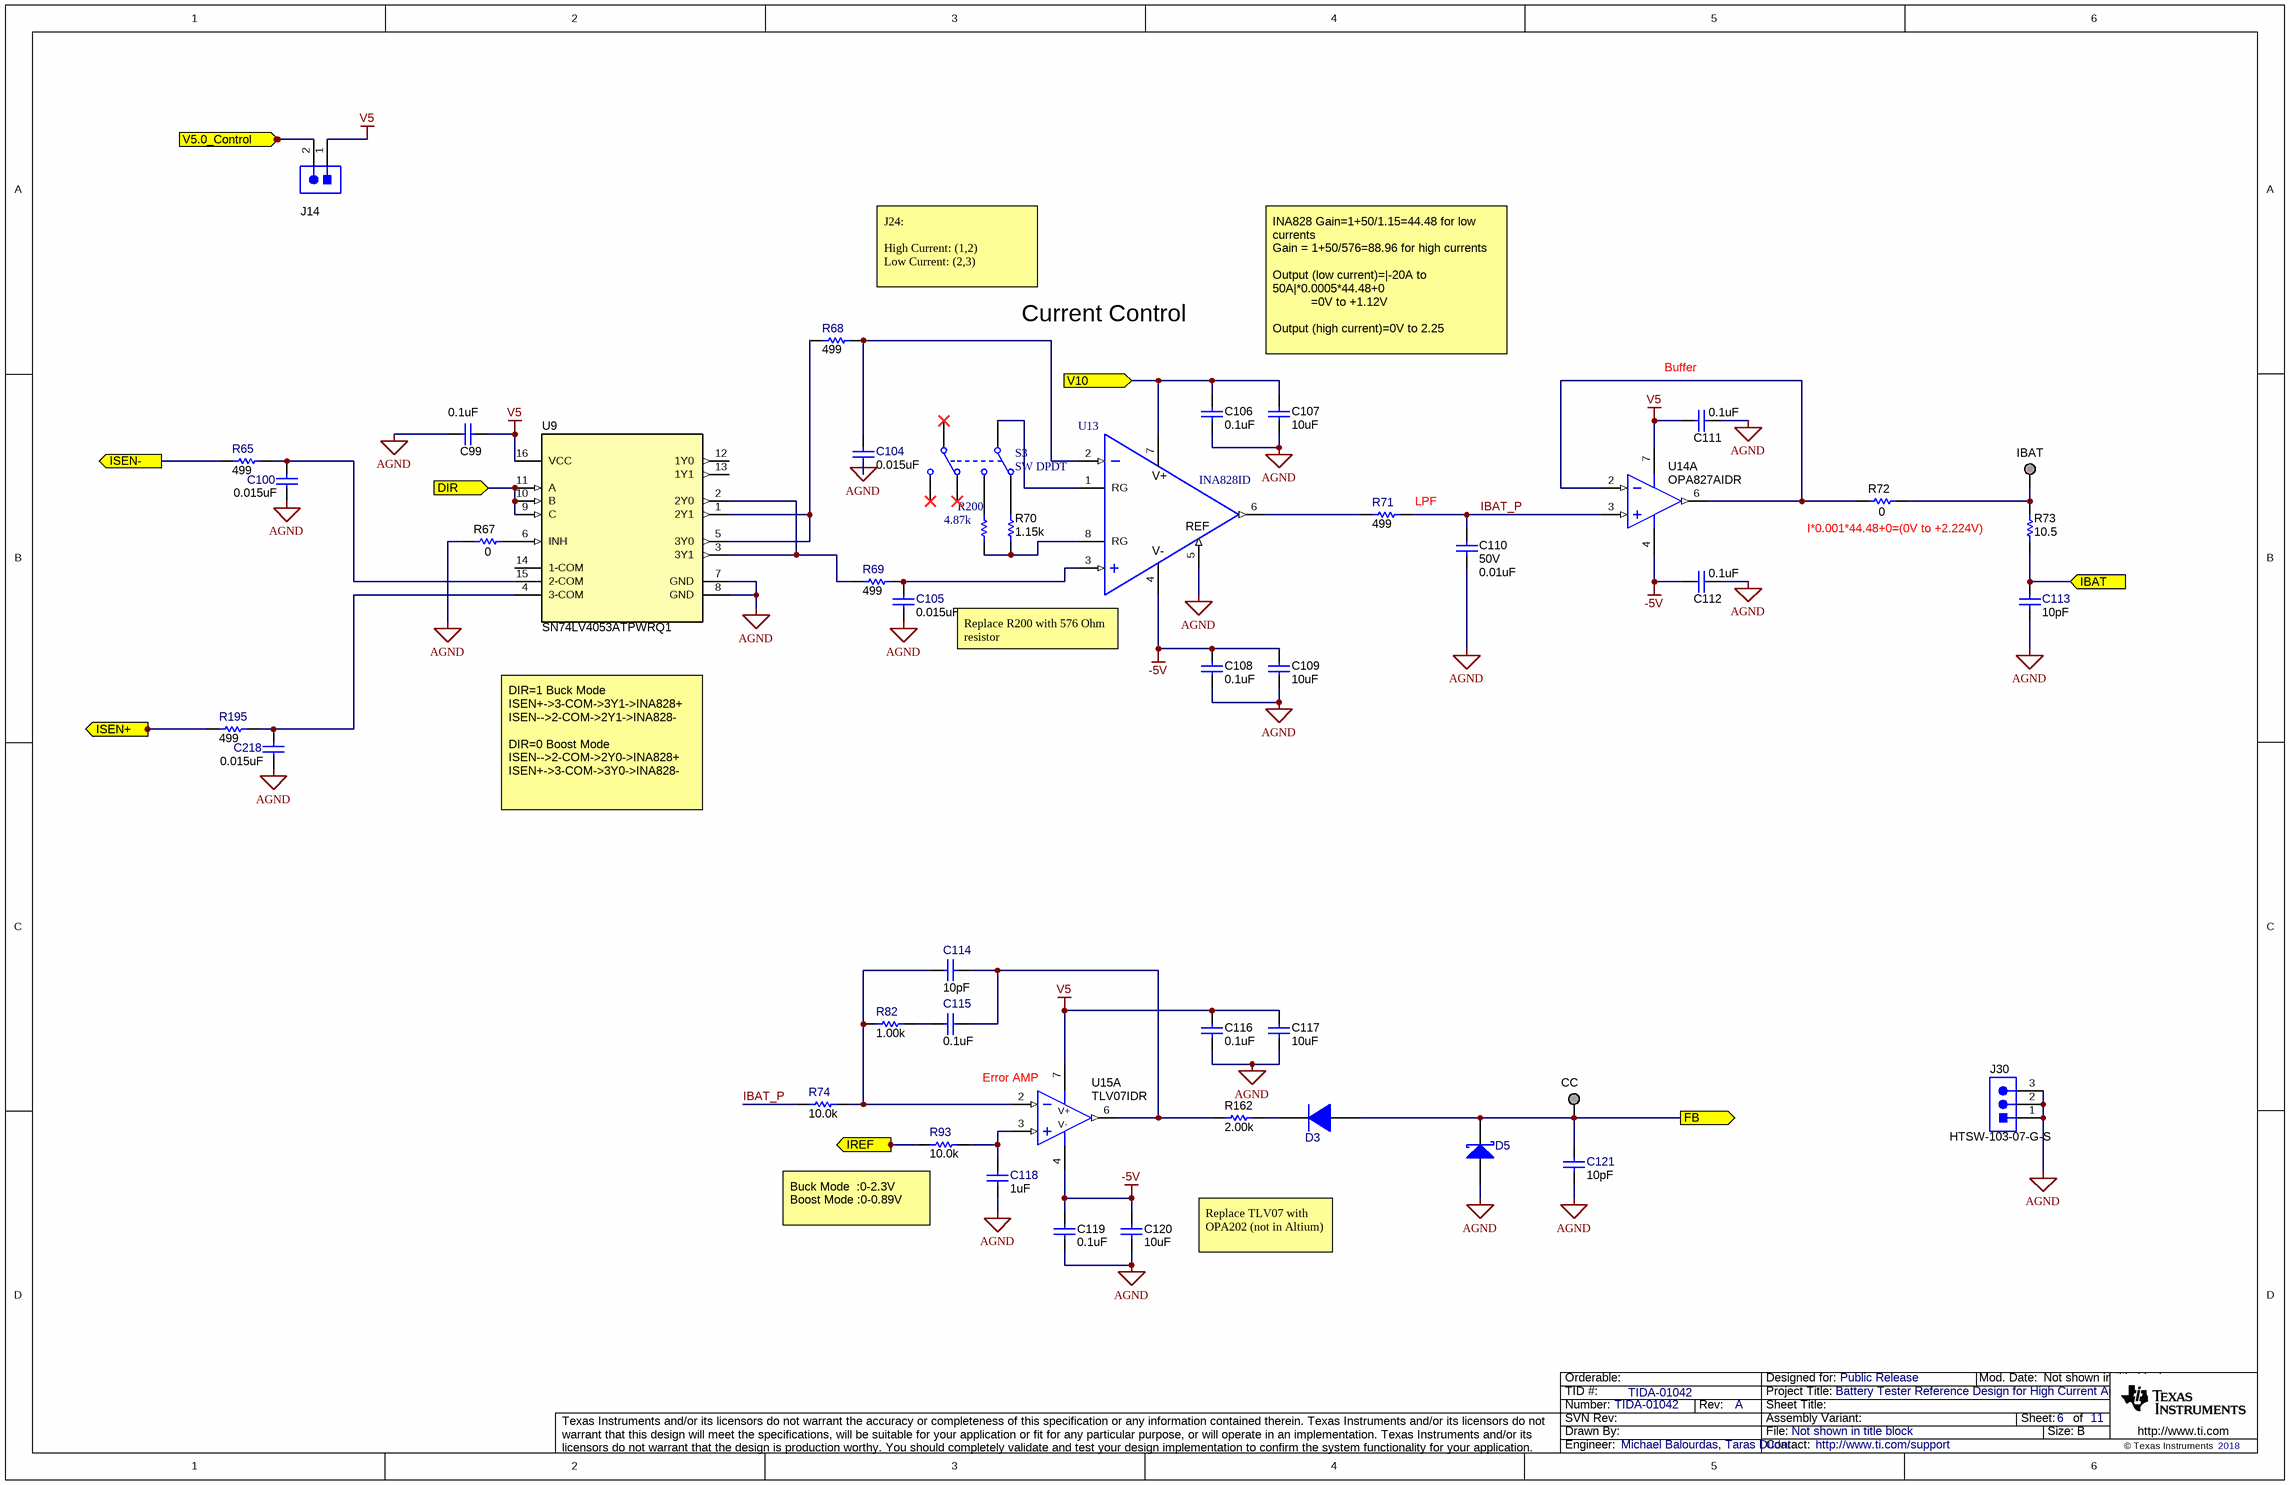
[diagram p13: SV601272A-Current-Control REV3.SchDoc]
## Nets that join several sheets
-0.2V: SV601272A-ADC (U19.6 U20.6), SV601272A-Bias (C228.1 C229.1 L8.1)
-5V: SV601272A-Analog (C97.1 C189.1 U2.4 U8.4), SV601272A-Bias (J16.1), SV601272A-Current-Control REV3 (8 pins)
AGND: SV601272A-Analog (17 pins), SV601272A-DAC (14 pins), SV601272A-ADC (44 pins), SV601272A-TM4C_Power (R147.2), SV601272A-Controller2 (45 pins), SV601272A-Controller1 (46 pins), SV601272A-Bias (28 pins), SV601272A-Current-Control REV3 (27 pins)
AVDD: SV601272A-DAC (C126.1 C127.1 U17.3), SV601272A-ADC (13 pins), SV601272A-Bias (R165.2)
DGND: SV601272A-TM4C_Main (24 pins), SV601272A-TM4C_Power (28 pins)
DVDD_3.3V: SV601272A-DAC (C128.1 J17.5 R99.1), SV601272A-ADC (10 pins), SV601272A-TM4C_Main (23 pins), SV601272A-TM4C_Power (14 pins)
PGND: SV601272A-Controller2 (C193.2 NT3.2 U6.18), SV601272A-Power2 REV2 (20 pins), SV601272A-Controller1 (C10.2 NT1.2 U1.18), SV601272A-Bias (15 pins), SV601272A-Power (46 pins)
V_HV: SV601272A-Controller2 (C33.1 J13.1 U6.6), SV601272A-Power2 REV2 (16 pins), SV601272A-Controller1 (C6.1 J1.1 U1.6), SV601272A-Bias (9 pins), SV601272A-Power (28 pins)
V_LV: SV601272A-Analog (J35.2), SV601272A-Controller2 (J13.3), SV601272A-Controller1 (J1.3), SV601272A-Power (15 pins)
VCC: SV601272A-Analog (C96.1 U8.7), SV601272A-DAC (L4.1), SV601272A-Controller2 (6 pins), SV601272A-Controller1 (6 pins), SV601272A-Bias (5 pins), SV601272A-Current-Control REV3 (C106.1 C107.1 U13.7)
VCCA: SV601272A-Controller2 (C194.1 R159.1 U6.31), SV601272A-Controller1 (C11.1 R14.1 U1.31)
VINX: SV601272A-Controller2 (R8.1 R43.1 U6.4), SV601272A-Controller1 (R1.1 R5.1 U1.4)
CS1A: SV601272A-Controller1 (C72.1 C80.1 U1.36), SV601272A-Power (R56.1)
CS1B: SV601272A-Controller1 (C73.1 C80.2 U1.35), SV601272A-Power (R57.1)
CS2A: SV601272A-Controller1 (C75.1 C81.2 U1.1), SV601272A-Power (R58.1)
CS2B: SV601272A-Controller1 (C74.1 C81.1 U1.2), SV601272A-Power (R59.1)
CS3A: SV601272A-Controller2 (C95.1 C190.1 U6.36), SV601272A-Power2 REV2 (R177.1)
CS3B: SV601272A-Controller2 (C95.2 C191.1 U6.35), SV601272A-Power2 REV2 (R178.1)
CS4A: SV601272A-Controller2 (C198.2 C200.1 U6.1), SV601272A-Power2 REV2 (R186.1)
CS4B: SV601272A-Controller2 (C198.1 C199.1 U6.2), SV601272A-Power2 REV2 (R187.1)
DIR: SV601272A-Analog (U11.1 U12.1), SV601272A-Controller2 (R144.2 U6.44), SV601272A-Controller1 (J6.2 R102.2 U1.44), SV601272A-Current-Control REV3 (U9.9 U9.10 U9.11)
EN: SV601272A-Analog (U10.2 U11.2), SV601272A-Controller1 (J7.2 U1.39)
FB: SV601272A-Analog (R163.2), SV601272A-Controller2 (5 pins), SV601272A-Controller1 (5 pins), SV601272A-Current-Control REV3 (C121.2 CC.1 D3.2 D5.1)
HO1: SV601272A-Controller1 (U1.22), SV601272A-Power (R26.1 R30.1)
HO2: SV601272A-Controller1 (U1.15), SV601272A-Power (R37.1 R41.1)
HO3: SV601272A-Controller2 (U6.22), SV601272A-Power2 REV2 (R179.1 R183.1)
HO4: SV601272A-Controller2 (U6.15), SV601272A-Power2 REV2 (R190.1 R194.1)
I2C_SCL: SV601272A-TM4C_Main (U23.112), SV601272A-TM4C_Power (R152.1 U28.6)
I2C_SDA: SV601272A-TM4C_Main (U23.111), SV601272A-TM4C_Power (R151.1 U28.5)
I_TOTAL: SV601272A-Power2 REV2 (R173.2 R184.1), SV601272A-Power (R16.3 R21.2 R32.1)
IBAT: SV601272A-ADC (R114.1), SV601272A-Current-Control REV3 (C113.2 R73.1)
IREF: SV601272A-DAC (J18.2 J18.4), SV601272A-Current-Control REV3 (R93.1)
ISEN+: SV601272A-Power (R31.1 R63.1), SV601272A-Current-Control REV3 (R195.2)
ISEN-: SV601272A-Power (R42.1 R64.1), SV601272A-Current-Control REV3 (R65.2)
LO1: SV601272A-Controller1 (U1.20), SV601272A-Power (R27.1 R28.1)
LO2: SV601272A-Controller1 (U1.17), SV601272A-Power (R38.1 R39.1)
LO3: SV601272A-Controller2 (U6.20), SV601272A-Power2 REV2 (R180.1 R181.1)
LO4: SV601272A-Controller2 (U6.17), SV601272A-Power2 REV2 (R191.1 R192.1)
SPI_CS: SV601272A-ADC (J19.6), SV601272A-TM4C_Main (U23.36)
SPI_DONE: SV601272A-ADC (J19.12), SV601272A-TM4C_Main (U23.29)
SPI_DRDY: SV601272A-ADC (J19.10), SV601272A-TM4C_Main (U23.30)
SPI_MISO: SV601272A-ADC (J19.2), SV601272A-TM4C_Main (U23.38)
SPI_MOSI: SV601272A-ADC (J19.4), SV601272A-TM4C_Main (U23.37)
SPI_SCLK: SV601272A-ADC (J19.8), SV601272A-TM4C_Main (U23.35)
SW1: SV601272A-Controller1 (C7.1 U1.24), SV601272A-Power (7 pins)
SW2: SV601272A-Controller1 (C12.2 U1.13), SV601272A-Power (7 pins)
SW3: SV601272A-Controller2 (C192.1 U6.24), SV601272A-Power2 REV2 (7 pins)
SW4: SV601272A-Controller2 (C195.2 U6.13), SV601272A-Power2 REV2 (7 pins)
SYNC: SV601272A-Controller2 (U6.40), SV601272A-Controller1 (J2.7 J3.2 U1.41)
USBCLK: SV601272A-TM4C_Main (U23.92), SV601272A-TM4C_Power (U27.1)
USBD0: SV601272A-TM4C_Main (U23.81), SV601272A-TM4C_Power (U27.3)
USBD1: SV601272A-TM4C_Main (U23.82), SV601272A-TM4C_Power (U27.4)
USBD2: SV601272A-TM4C_Main (U23.83), SV601272A-TM4C_Power (U27.5)
USBD3: SV601272A-TM4C_Main (U23.84), SV601272A-TM4C_Power (U27.6)
USBD4: SV601272A-TM4C_Main (U23.85), SV601272A-TM4C_Power (U27.7)
USBD5: SV601272A-TM4C_Main (U23.86), SV601272A-TM4C_Power (U27.9)
USBD6: SV601272A-TM4C_Main (U23.106), SV601272A-TM4C_Power (U27.10)
USBD7: SV601272A-TM4C_Main (U23.105), SV601272A-TM4C_Power (U27.13)
USBDIR: SV601272A-TM4C_Main (U23.104), SV601272A-TM4C_Power (U27.31)
USBNXT: SV601272A-TM4C_Main (U23.103), SV601272A-TM4C_Power (U27.2)
USBRST: SV601272A-TM4C_Main (U23.18), SV601272A-TM4C_Power (R154.2 U27.27)
USBSTP: SV601272A-TM4C_Main (U23.91), SV601272A-TM4C_Power (U27.29)
UVLO: SV601272A-Controller2 (J28.15 R34.1 R45.2 R87.2), SV601272A-Controller1 (J2.15 R4.1 R6.2 R60.2), SV601272A-Bias (R53.1 U3.3 U4.3 U5.4)
V5.0_Control: SV601272A-Analog (J37.2), SV601272A-Controller2 (J25.1 J26.1), SV601272A-Controller1 (J6.1 J7.1 J8.1), SV601272A-Bias (5 pins), SV601272A-Current-Control REV3 (J14.2)
VBAT: SV601272A-Analog (C98.1 R52.1), SV601272A-ADC (R129.1)
VREF: SV601272A-Analog (R84.2), SV601272A-DAC (J18.6 J18.8)

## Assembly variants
001: not fitted R44 R102 R144 R160 R161 R168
